VERSION 5.8 ;
BUSBITCHARS "[]" ;
DIVIDERCHAR "/" ;
UNITS
    DATABASE MICRONS 1000 ;
END UNITS

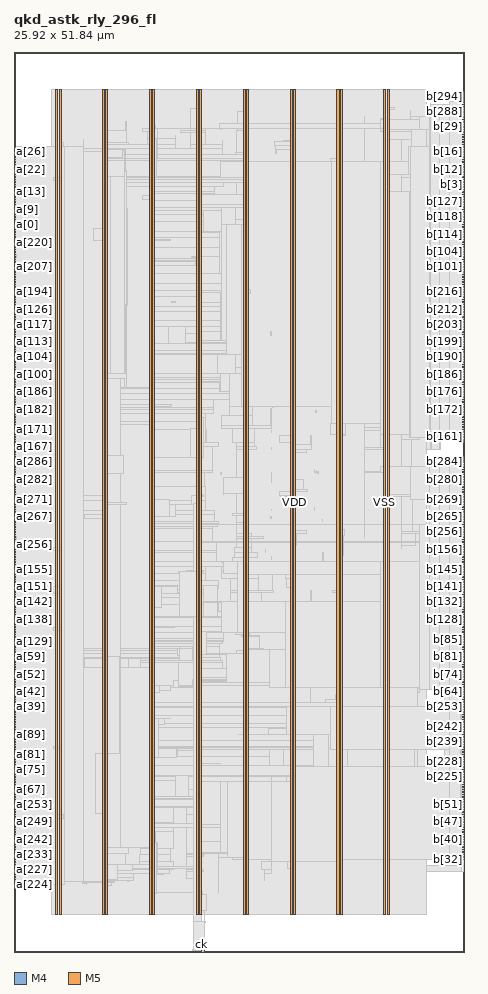
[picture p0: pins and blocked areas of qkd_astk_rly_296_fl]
MACRO qkd_astk_rly_296_fl
  FOREIGN qkd_astk_rly_296_fl 0 0 ;
  CLASS BLOCK ;
  SIZE 25.92 BY 51.84 ;
  PIN a[0]
    DIRECTION INPUT ;
    USE SIGNAL ;
    PORT
      LAYER M4 ;
        RECT  0 41.904 0.084 41.928 ;
    END
  END a[0]
  PIN a[100]
    DIRECTION INPUT ;
    USE SIGNAL ;
    PORT
      LAYER M4 ;
        RECT  0 33.264 0.084 33.288 ;
    END
  END a[100]
  PIN a[101]
    DIRECTION INPUT ;
    USE SIGNAL ;
    PORT
      LAYER M4 ;
        RECT  0 33.408 0.084 33.432 ;
    END
  END a[101]
  PIN a[102]
    DIRECTION INPUT ;
    USE SIGNAL ;
    PORT
      LAYER M4 ;
        RECT  0 33.552 0.084 33.576 ;
    END
  END a[102]
  PIN a[103]
    DIRECTION INPUT ;
    USE SIGNAL ;
    PORT
      LAYER M4 ;
        RECT  0 33.696 0.084 33.72 ;
    END
  END a[103]
  PIN a[104]
    DIRECTION INPUT ;
    USE SIGNAL ;
    PORT
      LAYER M4 ;
        RECT  0 33.84 0.084 33.864 ;
    END
  END a[104]
  PIN a[105]
    DIRECTION INPUT ;
    USE SIGNAL ;
    PORT
      LAYER M4 ;
        RECT  0 33.984 0.084 34.008 ;
    END
  END a[105]
  PIN a[106]
    DIRECTION INPUT ;
    USE SIGNAL ;
    PORT
      LAYER M4 ;
        RECT  0 34.128 0.084 34.152 ;
    END
  END a[106]
  PIN a[107]
    DIRECTION INPUT ;
    USE SIGNAL ;
    PORT
      LAYER M4 ;
        RECT  0 34.272 0.084 34.296 ;
    END
  END a[107]
  PIN a[108]
    DIRECTION INPUT ;
    USE SIGNAL ;
    PORT
      LAYER M4 ;
        RECT  0 34.416 0.084 34.44 ;
    END
  END a[108]
  PIN a[109]
    DIRECTION INPUT ;
    USE SIGNAL ;
    PORT
      LAYER M4 ;
        RECT  0 34.56 0.084 34.584 ;
    END
  END a[109]
  PIN a[10]
    DIRECTION INPUT ;
    USE SIGNAL ;
    PORT
      LAYER M4 ;
        RECT  0 43.344 0.084 43.368 ;
    END
  END a[10]
  PIN a[110]
    DIRECTION INPUT ;
    USE SIGNAL ;
    PORT
      LAYER M4 ;
        RECT  0 34.704 0.084 34.728 ;
    END
  END a[110]
  PIN a[111]
    DIRECTION INPUT ;
    USE SIGNAL ;
    PORT
      LAYER M4 ;
        RECT  0 34.848 0.084 34.872 ;
    END
  END a[111]
  PIN a[112]
    DIRECTION INPUT ;
    USE SIGNAL ;
    PORT
      LAYER M4 ;
        RECT  0 34.992 0.084 35.016 ;
    END
  END a[112]
  PIN a[113]
    DIRECTION INPUT ;
    USE SIGNAL ;
    PORT
      LAYER M4 ;
        RECT  0 35.136 0.084 35.16 ;
    END
  END a[113]
  PIN a[114]
    DIRECTION INPUT ;
    USE SIGNAL ;
    PORT
      LAYER M4 ;
        RECT  0 35.28 0.084 35.304 ;
    END
  END a[114]
  PIN a[115]
    DIRECTION INPUT ;
    USE SIGNAL ;
    PORT
      LAYER M4 ;
        RECT  0 35.424 0.084 35.448 ;
    END
  END a[115]
  PIN a[116]
    DIRECTION INPUT ;
    USE SIGNAL ;
    PORT
      LAYER M4 ;
        RECT  0 35.568 0.084 35.592 ;
    END
  END a[116]
  PIN a[117]
    DIRECTION INPUT ;
    USE SIGNAL ;
    PORT
      LAYER M4 ;
        RECT  0 35.712 0.084 35.736 ;
    END
  END a[117]
  PIN a[118]
    DIRECTION INPUT ;
    USE SIGNAL ;
    PORT
      LAYER M4 ;
        RECT  0 35.856 0.084 35.88 ;
    END
  END a[118]
  PIN a[119]
    DIRECTION INPUT ;
    USE SIGNAL ;
    PORT
      LAYER M4 ;
        RECT  0 36 0.084 36.024 ;
    END
  END a[119]
  PIN a[11]
    DIRECTION INPUT ;
    USE SIGNAL ;
    PORT
      LAYER M4 ;
        RECT  0 43.488 0.084 43.512 ;
    END
  END a[11]
  PIN a[120]
    DIRECTION INPUT ;
    USE SIGNAL ;
    PORT
      LAYER M4 ;
        RECT  0 36.144 0.084 36.168 ;
    END
  END a[120]
  PIN a[121]
    DIRECTION INPUT ;
    USE SIGNAL ;
    PORT
      LAYER M4 ;
        RECT  0 36.288 0.084 36.312 ;
    END
  END a[121]
  PIN a[122]
    DIRECTION INPUT ;
    USE SIGNAL ;
    PORT
      LAYER M4 ;
        RECT  0 36.432 0.084 36.456 ;
    END
  END a[122]
  PIN a[123]
    DIRECTION INPUT ;
    USE SIGNAL ;
    PORT
      LAYER M4 ;
        RECT  0 36.576 0.084 36.6 ;
    END
  END a[123]
  PIN a[124]
    DIRECTION INPUT ;
    USE SIGNAL ;
    PORT
      LAYER M4 ;
        RECT  0 36.72 0.084 36.744 ;
    END
  END a[124]
  PIN a[125]
    DIRECTION INPUT ;
    USE SIGNAL ;
    PORT
      LAYER M4 ;
        RECT  0 36.864 0.084 36.888 ;
    END
  END a[125]
  PIN a[126]
    DIRECTION INPUT ;
    USE SIGNAL ;
    PORT
      LAYER M4 ;
        RECT  0 37.008 0.084 37.032 ;
    END
  END a[126]
  PIN a[127]
    DIRECTION INPUT ;
    USE SIGNAL ;
    PORT
      LAYER M4 ;
        RECT  0 37.152 0.084 37.176 ;
    END
  END a[127]
  PIN a[128]
    DIRECTION INPUT ;
    USE SIGNAL ;
    PORT
      LAYER M4 ;
        RECT  0 17.712 0.084 17.736 ;
    END
  END a[128]
  PIN a[129]
    DIRECTION INPUT ;
    USE SIGNAL ;
    PORT
      LAYER M4 ;
        RECT  0 17.856 0.084 17.88 ;
    END
  END a[129]
  PIN a[12]
    DIRECTION INPUT ;
    USE SIGNAL ;
    PORT
      LAYER M4 ;
        RECT  0 43.632 0.084 43.656 ;
    END
  END a[12]
  PIN a[130]
    DIRECTION INPUT ;
    USE SIGNAL ;
    PORT
      LAYER M4 ;
        RECT  0 18 0.084 18.024 ;
    END
  END a[130]
  PIN a[131]
    DIRECTION INPUT ;
    USE SIGNAL ;
    PORT
      LAYER M4 ;
        RECT  0 18.144 0.084 18.168 ;
    END
  END a[131]
  PIN a[132]
    DIRECTION INPUT ;
    USE SIGNAL ;
    PORT
      LAYER M4 ;
        RECT  0 18.288 0.084 18.312 ;
    END
  END a[132]
  PIN a[133]
    DIRECTION INPUT ;
    USE SIGNAL ;
    PORT
      LAYER M4 ;
        RECT  0 18.432 0.084 18.456 ;
    END
  END a[133]
  PIN a[134]
    DIRECTION INPUT ;
    USE SIGNAL ;
    PORT
      LAYER M4 ;
        RECT  0 18.576 0.084 18.6 ;
    END
  END a[134]
  PIN a[135]
    DIRECTION INPUT ;
    USE SIGNAL ;
    PORT
      LAYER M4 ;
        RECT  0 18.72 0.084 18.744 ;
    END
  END a[135]
  PIN a[136]
    DIRECTION INPUT ;
    USE SIGNAL ;
    PORT
      LAYER M4 ;
        RECT  0 18.864 0.084 18.888 ;
    END
  END a[136]
  PIN a[137]
    DIRECTION INPUT ;
    USE SIGNAL ;
    PORT
      LAYER M4 ;
        RECT  0 19.008 0.084 19.032 ;
    END
  END a[137]
  PIN a[138]
    DIRECTION INPUT ;
    USE SIGNAL ;
    PORT
      LAYER M4 ;
        RECT  0 19.152 0.084 19.176 ;
    END
  END a[138]
  PIN a[139]
    DIRECTION INPUT ;
    USE SIGNAL ;
    PORT
      LAYER M4 ;
        RECT  0 19.296 0.084 19.32 ;
    END
  END a[139]
  PIN a[13]
    DIRECTION INPUT ;
    USE SIGNAL ;
    PORT
      LAYER M4 ;
        RECT  0 43.776 0.084 43.8 ;
    END
  END a[13]
  PIN a[140]
    DIRECTION INPUT ;
    USE SIGNAL ;
    PORT
      LAYER M4 ;
        RECT  0 19.44 0.084 19.464 ;
    END
  END a[140]
  PIN a[141]
    DIRECTION INPUT ;
    USE SIGNAL ;
    PORT
      LAYER M4 ;
        RECT  0 19.584 0.084 19.608 ;
    END
  END a[141]
  PIN a[142]
    DIRECTION INPUT ;
    USE SIGNAL ;
    PORT
      LAYER M4 ;
        RECT  0 19.728 0.084 19.752 ;
    END
  END a[142]
  PIN a[143]
    DIRECTION INPUT ;
    USE SIGNAL ;
    PORT
      LAYER M4 ;
        RECT  0 19.872 0.084 19.896 ;
    END
  END a[143]
  PIN a[144]
    DIRECTION INPUT ;
    USE SIGNAL ;
    PORT
      LAYER M4 ;
        RECT  0 20.016 0.084 20.04 ;
    END
  END a[144]
  PIN a[145]
    DIRECTION INPUT ;
    USE SIGNAL ;
    PORT
      LAYER M4 ;
        RECT  0 20.16 0.084 20.184 ;
    END
  END a[145]
  PIN a[146]
    DIRECTION INPUT ;
    USE SIGNAL ;
    PORT
      LAYER M4 ;
        RECT  0 20.304 0.084 20.328 ;
    END
  END a[146]
  PIN a[147]
    DIRECTION INPUT ;
    USE SIGNAL ;
    PORT
      LAYER M4 ;
        RECT  0 20.448 0.084 20.472 ;
    END
  END a[147]
  PIN a[148]
    DIRECTION INPUT ;
    USE SIGNAL ;
    PORT
      LAYER M4 ;
        RECT  0 20.592 0.084 20.616 ;
    END
  END a[148]
  PIN a[149]
    DIRECTION INPUT ;
    USE SIGNAL ;
    PORT
      LAYER M4 ;
        RECT  0 20.736 0.084 20.76 ;
    END
  END a[149]
  PIN a[14]
    DIRECTION INPUT ;
    USE SIGNAL ;
    PORT
      LAYER M4 ;
        RECT  0 43.92 0.084 43.944 ;
    END
  END a[14]
  PIN a[150]
    DIRECTION INPUT ;
    USE SIGNAL ;
    PORT
      LAYER M4 ;
        RECT  0 20.88 0.084 20.904 ;
    END
  END a[150]
  PIN a[151]
    DIRECTION INPUT ;
    USE SIGNAL ;
    PORT
      LAYER M4 ;
        RECT  0 21.024 0.084 21.048 ;
    END
  END a[151]
  PIN a[152]
    DIRECTION INPUT ;
    USE SIGNAL ;
    PORT
      LAYER M4 ;
        RECT  0 21.168 0.084 21.192 ;
    END
  END a[152]
  PIN a[153]
    DIRECTION INPUT ;
    USE SIGNAL ;
    PORT
      LAYER M4 ;
        RECT  0 21.312 0.084 21.336 ;
    END
  END a[153]
  PIN a[154]
    DIRECTION INPUT ;
    USE SIGNAL ;
    PORT
      LAYER M4 ;
        RECT  0 21.456 0.084 21.48 ;
    END
  END a[154]
  PIN a[155]
    DIRECTION INPUT ;
    USE SIGNAL ;
    PORT
      LAYER M4 ;
        RECT  0 21.6 0.084 21.624 ;
    END
  END a[155]
  PIN a[156]
    DIRECTION INPUT ;
    USE SIGNAL ;
    PORT
      LAYER M4 ;
        RECT  0 21.744 0.084 21.768 ;
    END
  END a[156]
  PIN a[157]
    DIRECTION INPUT ;
    USE SIGNAL ;
    PORT
      LAYER M4 ;
        RECT  0 21.888 0.084 21.912 ;
    END
  END a[157]
  PIN a[158]
    DIRECTION INPUT ;
    USE SIGNAL ;
    PORT
      LAYER M4 ;
        RECT  0 22.032 0.084 22.056 ;
    END
  END a[158]
  PIN a[159]
    DIRECTION INPUT ;
    USE SIGNAL ;
    PORT
      LAYER M4 ;
        RECT  0 22.176 0.084 22.2 ;
    END
  END a[159]
  PIN a[15]
    DIRECTION INPUT ;
    USE SIGNAL ;
    PORT
      LAYER M4 ;
        RECT  0 44.064 0.084 44.088 ;
    END
  END a[15]
  PIN a[160]
    DIRECTION INPUT ;
    USE SIGNAL ;
    PORT
      LAYER M4 ;
        RECT  0 28.08 0.084 28.104 ;
    END
  END a[160]
  PIN a[161]
    DIRECTION INPUT ;
    USE SIGNAL ;
    PORT
      LAYER M4 ;
        RECT  0 28.224 0.084 28.248 ;
    END
  END a[161]
  PIN a[162]
    DIRECTION INPUT ;
    USE SIGNAL ;
    PORT
      LAYER M4 ;
        RECT  0 28.368 0.084 28.392 ;
    END
  END a[162]
  PIN a[163]
    DIRECTION INPUT ;
    USE SIGNAL ;
    PORT
      LAYER M4 ;
        RECT  0 28.512 0.084 28.536 ;
    END
  END a[163]
  PIN a[164]
    DIRECTION INPUT ;
    USE SIGNAL ;
    PORT
      LAYER M4 ;
        RECT  0 28.656 0.084 28.68 ;
    END
  END a[164]
  PIN a[165]
    DIRECTION INPUT ;
    USE SIGNAL ;
    PORT
      LAYER M4 ;
        RECT  0 28.8 0.084 28.824 ;
    END
  END a[165]
  PIN a[166]
    DIRECTION INPUT ;
    USE SIGNAL ;
    PORT
      LAYER M4 ;
        RECT  0 28.944 0.084 28.968 ;
    END
  END a[166]
  PIN a[167]
    DIRECTION INPUT ;
    USE SIGNAL ;
    PORT
      LAYER M4 ;
        RECT  0 29.088 0.084 29.112 ;
    END
  END a[167]
  PIN a[168]
    DIRECTION INPUT ;
    USE SIGNAL ;
    PORT
      LAYER M4 ;
        RECT  0 29.232 0.084 29.256 ;
    END
  END a[168]
  PIN a[169]
    DIRECTION INPUT ;
    USE SIGNAL ;
    PORT
      LAYER M4 ;
        RECT  0 29.376 0.084 29.4 ;
    END
  END a[169]
  PIN a[16]
    DIRECTION INPUT ;
    USE SIGNAL ;
    PORT
      LAYER M4 ;
        RECT  0 44.208 0.084 44.232 ;
    END
  END a[16]
  PIN a[170]
    DIRECTION INPUT ;
    USE SIGNAL ;
    PORT
      LAYER M4 ;
        RECT  0 29.52 0.084 29.544 ;
    END
  END a[170]
  PIN a[171]
    DIRECTION INPUT ;
    USE SIGNAL ;
    PORT
      LAYER M4 ;
        RECT  0 29.664 0.084 29.688 ;
    END
  END a[171]
  PIN a[172]
    DIRECTION INPUT ;
    USE SIGNAL ;
    PORT
      LAYER M4 ;
        RECT  0 29.808 0.084 29.832 ;
    END
  END a[172]
  PIN a[173]
    DIRECTION INPUT ;
    USE SIGNAL ;
    PORT
      LAYER M4 ;
        RECT  0 29.952 0.084 29.976 ;
    END
  END a[173]
  PIN a[174]
    DIRECTION INPUT ;
    USE SIGNAL ;
    PORT
      LAYER M4 ;
        RECT  0 30.096 0.084 30.12 ;
    END
  END a[174]
  PIN a[175]
    DIRECTION INPUT ;
    USE SIGNAL ;
    PORT
      LAYER M4 ;
        RECT  0 30.24 0.084 30.264 ;
    END
  END a[175]
  PIN a[176]
    DIRECTION INPUT ;
    USE SIGNAL ;
    PORT
      LAYER M4 ;
        RECT  0 30.384 0.084 30.408 ;
    END
  END a[176]
  PIN a[177]
    DIRECTION INPUT ;
    USE SIGNAL ;
    PORT
      LAYER M4 ;
        RECT  0 30.528 0.084 30.552 ;
    END
  END a[177]
  PIN a[178]
    DIRECTION INPUT ;
    USE SIGNAL ;
    PORT
      LAYER M4 ;
        RECT  0 30.672 0.084 30.696 ;
    END
  END a[178]
  PIN a[179]
    DIRECTION INPUT ;
    USE SIGNAL ;
    PORT
      LAYER M4 ;
        RECT  0 30.816 0.084 30.84 ;
    END
  END a[179]
  PIN a[17]
    DIRECTION INPUT ;
    USE SIGNAL ;
    PORT
      LAYER M4 ;
        RECT  0 44.352 0.084 44.376 ;
    END
  END a[17]
  PIN a[180]
    DIRECTION INPUT ;
    USE SIGNAL ;
    PORT
      LAYER M4 ;
        RECT  0 30.96 0.084 30.984 ;
    END
  END a[180]
  PIN a[181]
    DIRECTION INPUT ;
    USE SIGNAL ;
    PORT
      LAYER M4 ;
        RECT  0 31.104 0.084 31.128 ;
    END
  END a[181]
  PIN a[182]
    DIRECTION INPUT ;
    USE SIGNAL ;
    PORT
      LAYER M4 ;
        RECT  0 31.248 0.084 31.272 ;
    END
  END a[182]
  PIN a[183]
    DIRECTION INPUT ;
    USE SIGNAL ;
    PORT
      LAYER M4 ;
        RECT  0 31.392 0.084 31.416 ;
    END
  END a[183]
  PIN a[184]
    DIRECTION INPUT ;
    USE SIGNAL ;
    PORT
      LAYER M4 ;
        RECT  0 31.536 0.084 31.56 ;
    END
  END a[184]
  PIN a[185]
    DIRECTION INPUT ;
    USE SIGNAL ;
    PORT
      LAYER M4 ;
        RECT  0 31.68 0.084 31.704 ;
    END
  END a[185]
  PIN a[186]
    DIRECTION INPUT ;
    USE SIGNAL ;
    PORT
      LAYER M4 ;
        RECT  0 31.824 0.084 31.848 ;
    END
  END a[186]
  PIN a[187]
    DIRECTION INPUT ;
    USE SIGNAL ;
    PORT
      LAYER M4 ;
        RECT  0 31.968 0.084 31.992 ;
    END
  END a[187]
  PIN a[188]
    DIRECTION INPUT ;
    USE SIGNAL ;
    PORT
      LAYER M4 ;
        RECT  0 32.112 0.084 32.136 ;
    END
  END a[188]
  PIN a[189]
    DIRECTION INPUT ;
    USE SIGNAL ;
    PORT
      LAYER M4 ;
        RECT  0 32.256 0.084 32.28 ;
    END
  END a[189]
  PIN a[18]
    DIRECTION INPUT ;
    USE SIGNAL ;
    PORT
      LAYER M4 ;
        RECT  0 44.496 0.084 44.52 ;
    END
  END a[18]
  PIN a[190]
    DIRECTION INPUT ;
    USE SIGNAL ;
    PORT
      LAYER M4 ;
        RECT  0 32.4 0.084 32.424 ;
    END
  END a[190]
  PIN a[191]
    DIRECTION INPUT ;
    USE SIGNAL ;
    PORT
      LAYER M4 ;
        RECT  0 32.544 0.084 32.568 ;
    END
  END a[191]
  PIN a[192]
    DIRECTION INPUT ;
    USE SIGNAL ;
    PORT
      LAYER M4 ;
        RECT  0 37.296 0.084 37.32 ;
    END
  END a[192]
  PIN a[193]
    DIRECTION INPUT ;
    USE SIGNAL ;
    PORT
      LAYER M4 ;
        RECT  0 37.44 0.084 37.464 ;
    END
  END a[193]
  PIN a[194]
    DIRECTION INPUT ;
    USE SIGNAL ;
    PORT
      LAYER M4 ;
        RECT  0 37.584 0.084 37.608 ;
    END
  END a[194]
  PIN a[195]
    DIRECTION INPUT ;
    USE SIGNAL ;
    PORT
      LAYER M4 ;
        RECT  0 37.728 0.084 37.752 ;
    END
  END a[195]
  PIN a[196]
    DIRECTION INPUT ;
    USE SIGNAL ;
    PORT
      LAYER M4 ;
        RECT  0 37.872 0.084 37.896 ;
    END
  END a[196]
  PIN a[197]
    DIRECTION INPUT ;
    USE SIGNAL ;
    PORT
      LAYER M4 ;
        RECT  0 38.016 0.084 38.04 ;
    END
  END a[197]
  PIN a[198]
    DIRECTION INPUT ;
    USE SIGNAL ;
    PORT
      LAYER M4 ;
        RECT  0 38.16 0.084 38.184 ;
    END
  END a[198]
  PIN a[199]
    DIRECTION INPUT ;
    USE SIGNAL ;
    PORT
      LAYER M4 ;
        RECT  0 38.304 0.084 38.328 ;
    END
  END a[199]
  PIN a[19]
    DIRECTION INPUT ;
    USE SIGNAL ;
    PORT
      LAYER M4 ;
        RECT  0 44.64 0.084 44.664 ;
    END
  END a[19]
  PIN a[1]
    DIRECTION INPUT ;
    USE SIGNAL ;
    PORT
      LAYER M4 ;
        RECT  0 42.048 0.084 42.072 ;
    END
  END a[1]
  PIN a[200]
    DIRECTION INPUT ;
    USE SIGNAL ;
    PORT
      LAYER M4 ;
        RECT  0 38.448 0.084 38.472 ;
    END
  END a[200]
  PIN a[201]
    DIRECTION INPUT ;
    USE SIGNAL ;
    PORT
      LAYER M4 ;
        RECT  0 38.592 0.084 38.616 ;
    END
  END a[201]
  PIN a[202]
    DIRECTION INPUT ;
    USE SIGNAL ;
    PORT
      LAYER M4 ;
        RECT  0 38.736 0.084 38.76 ;
    END
  END a[202]
  PIN a[203]
    DIRECTION INPUT ;
    USE SIGNAL ;
    PORT
      LAYER M4 ;
        RECT  0 38.88 0.084 38.904 ;
    END
  END a[203]
  PIN a[204]
    DIRECTION INPUT ;
    USE SIGNAL ;
    PORT
      LAYER M4 ;
        RECT  0 39.024 0.084 39.048 ;
    END
  END a[204]
  PIN a[205]
    DIRECTION INPUT ;
    USE SIGNAL ;
    PORT
      LAYER M4 ;
        RECT  0 39.168 0.084 39.192 ;
    END
  END a[205]
  PIN a[206]
    DIRECTION INPUT ;
    USE SIGNAL ;
    PORT
      LAYER M4 ;
        RECT  0 39.312 0.084 39.336 ;
    END
  END a[206]
  PIN a[207]
    DIRECTION INPUT ;
    USE SIGNAL ;
    PORT
      LAYER M4 ;
        RECT  0 39.456 0.084 39.48 ;
    END
  END a[207]
  PIN a[208]
    DIRECTION INPUT ;
    USE SIGNAL ;
    PORT
      LAYER M4 ;
        RECT  0 39.6 0.084 39.624 ;
    END
  END a[208]
  PIN a[209]
    DIRECTION INPUT ;
    USE SIGNAL ;
    PORT
      LAYER M4 ;
        RECT  0 39.744 0.084 39.768 ;
    END
  END a[209]
  PIN a[20]
    DIRECTION INPUT ;
    USE SIGNAL ;
    PORT
      LAYER M4 ;
        RECT  0 44.784 0.084 44.808 ;
    END
  END a[20]
  PIN a[210]
    DIRECTION INPUT ;
    USE SIGNAL ;
    PORT
      LAYER M4 ;
        RECT  0 39.888 0.084 39.912 ;
    END
  END a[210]
  PIN a[211]
    DIRECTION INPUT ;
    USE SIGNAL ;
    PORT
      LAYER M4 ;
        RECT  0 40.032 0.084 40.056 ;
    END
  END a[211]
  PIN a[212]
    DIRECTION INPUT ;
    USE SIGNAL ;
    PORT
      LAYER M4 ;
        RECT  0 40.176 0.084 40.2 ;
    END
  END a[212]
  PIN a[213]
    DIRECTION INPUT ;
    USE SIGNAL ;
    PORT
      LAYER M4 ;
        RECT  0 40.32 0.084 40.344 ;
    END
  END a[213]
  PIN a[214]
    DIRECTION INPUT ;
    USE SIGNAL ;
    PORT
      LAYER M4 ;
        RECT  0 40.464 0.084 40.488 ;
    END
  END a[214]
  PIN a[215]
    DIRECTION INPUT ;
    USE SIGNAL ;
    PORT
      LAYER M4 ;
        RECT  0 40.608 0.084 40.632 ;
    END
  END a[215]
  PIN a[216]
    DIRECTION INPUT ;
    USE SIGNAL ;
    PORT
      LAYER M4 ;
        RECT  0 40.752 0.084 40.776 ;
    END
  END a[216]
  PIN a[217]
    DIRECTION INPUT ;
    USE SIGNAL ;
    PORT
      LAYER M4 ;
        RECT  0 40.896 0.084 40.92 ;
    END
  END a[217]
  PIN a[218]
    DIRECTION INPUT ;
    USE SIGNAL ;
    PORT
      LAYER M4 ;
        RECT  0 41.04 0.084 41.064 ;
    END
  END a[218]
  PIN a[219]
    DIRECTION INPUT ;
    USE SIGNAL ;
    PORT
      LAYER M4 ;
        RECT  0 41.184 0.084 41.208 ;
    END
  END a[219]
  PIN a[21]
    DIRECTION INPUT ;
    USE SIGNAL ;
    PORT
      LAYER M4 ;
        RECT  0 44.928 0.084 44.952 ;
    END
  END a[21]
  PIN a[220]
    DIRECTION INPUT ;
    USE SIGNAL ;
    PORT
      LAYER M4 ;
        RECT  0 41.328 0.084 41.352 ;
    END
  END a[220]
  PIN a[221]
    DIRECTION INPUT ;
    USE SIGNAL ;
    PORT
      LAYER M4 ;
        RECT  0 41.472 0.084 41.496 ;
    END
  END a[221]
  PIN a[222]
    DIRECTION INPUT ;
    USE SIGNAL ;
    PORT
      LAYER M4 ;
        RECT  0 41.616 0.084 41.64 ;
    END
  END a[222]
  PIN a[223]
    DIRECTION INPUT ;
    USE SIGNAL ;
    PORT
      LAYER M4 ;
        RECT  0 41.76 0.084 41.784 ;
    END
  END a[223]
  PIN a[224]
    DIRECTION INPUT ;
    USE SIGNAL ;
    PORT
      LAYER M4 ;
        RECT  0 3.888 0.084 3.912 ;
    END
  END a[224]
  PIN a[225]
    DIRECTION INPUT ;
    USE SIGNAL ;
    PORT
      LAYER M4 ;
        RECT  0 4.032 0.084 4.056 ;
    END
  END a[225]
  PIN a[226]
    DIRECTION INPUT ;
    USE SIGNAL ;
    PORT
      LAYER M4 ;
        RECT  0 4.176 0.084 4.2 ;
    END
  END a[226]
  PIN a[227]
    DIRECTION INPUT ;
    USE SIGNAL ;
    PORT
      LAYER M4 ;
        RECT  0 4.32 0.084 4.344 ;
    END
  END a[227]
  PIN a[228]
    DIRECTION INPUT ;
    USE SIGNAL ;
    PORT
      LAYER M4 ;
        RECT  0 4.464 0.084 4.488 ;
    END
  END a[228]
  PIN a[229]
    DIRECTION INPUT ;
    USE SIGNAL ;
    PORT
      LAYER M4 ;
        RECT  0 4.608 0.084 4.632 ;
    END
  END a[229]
  PIN a[22]
    DIRECTION INPUT ;
    USE SIGNAL ;
    PORT
      LAYER M4 ;
        RECT  0 45.072 0.084 45.096 ;
    END
  END a[22]
  PIN a[230]
    DIRECTION INPUT ;
    USE SIGNAL ;
    PORT
      LAYER M4 ;
        RECT  0 4.752 0.084 4.776 ;
    END
  END a[230]
  PIN a[231]
    DIRECTION INPUT ;
    USE SIGNAL ;
    PORT
      LAYER M4 ;
        RECT  0 4.896 0.084 4.92 ;
    END
  END a[231]
  PIN a[232]
    DIRECTION INPUT ;
    USE SIGNAL ;
    PORT
      LAYER M4 ;
        RECT  0 5.04 0.084 5.064 ;
    END
  END a[232]
  PIN a[233]
    DIRECTION INPUT ;
    USE SIGNAL ;
    PORT
      LAYER M4 ;
        RECT  0 5.184 0.084 5.208 ;
    END
  END a[233]
  PIN a[234]
    DIRECTION INPUT ;
    USE SIGNAL ;
    PORT
      LAYER M4 ;
        RECT  0 5.328 0.084 5.352 ;
    END
  END a[234]
  PIN a[235]
    DIRECTION INPUT ;
    USE SIGNAL ;
    PORT
      LAYER M4 ;
        RECT  0 5.472 0.084 5.496 ;
    END
  END a[235]
  PIN a[236]
    DIRECTION INPUT ;
    USE SIGNAL ;
    PORT
      LAYER M4 ;
        RECT  0 5.616 0.084 5.64 ;
    END
  END a[236]
  PIN a[237]
    DIRECTION INPUT ;
    USE SIGNAL ;
    PORT
      LAYER M4 ;
        RECT  0 5.76 0.084 5.784 ;
    END
  END a[237]
  PIN a[238]
    DIRECTION INPUT ;
    USE SIGNAL ;
    PORT
      LAYER M4 ;
        RECT  0 5.904 0.084 5.928 ;
    END
  END a[238]
  PIN a[239]
    DIRECTION INPUT ;
    USE SIGNAL ;
    PORT
      LAYER M4 ;
        RECT  0 6.048 0.084 6.072 ;
    END
  END a[239]
  PIN a[23]
    DIRECTION INPUT ;
    USE SIGNAL ;
    PORT
      LAYER M4 ;
        RECT  0 45.216 0.084 45.24 ;
    END
  END a[23]
  PIN a[240]
    DIRECTION INPUT ;
    USE SIGNAL ;
    PORT
      LAYER M4 ;
        RECT  0 6.192 0.084 6.216 ;
    END
  END a[240]
  PIN a[241]
    DIRECTION INPUT ;
    USE SIGNAL ;
    PORT
      LAYER M4 ;
        RECT  0 6.336 0.084 6.36 ;
    END
  END a[241]
  PIN a[242]
    DIRECTION INPUT ;
    USE SIGNAL ;
    PORT
      LAYER M4 ;
        RECT  0 6.48 0.084 6.504 ;
    END
  END a[242]
  PIN a[243]
    DIRECTION INPUT ;
    USE SIGNAL ;
    PORT
      LAYER M4 ;
        RECT  0 6.624 0.084 6.648 ;
    END
  END a[243]
  PIN a[244]
    DIRECTION INPUT ;
    USE SIGNAL ;
    PORT
      LAYER M4 ;
        RECT  0 6.768 0.084 6.792 ;
    END
  END a[244]
  PIN a[245]
    DIRECTION INPUT ;
    USE SIGNAL ;
    PORT
      LAYER M4 ;
        RECT  0 6.912 0.084 6.936 ;
    END
  END a[245]
  PIN a[246]
    DIRECTION INPUT ;
    USE SIGNAL ;
    PORT
      LAYER M4 ;
        RECT  0 7.056 0.084 7.08 ;
    END
  END a[246]
  PIN a[247]
    DIRECTION INPUT ;
    USE SIGNAL ;
    PORT
      LAYER M4 ;
        RECT  0 7.2 0.084 7.224 ;
    END
  END a[247]
  PIN a[248]
    DIRECTION INPUT ;
    USE SIGNAL ;
    PORT
      LAYER M4 ;
        RECT  0 7.344 0.084 7.368 ;
    END
  END a[248]
  PIN a[249]
    DIRECTION INPUT ;
    USE SIGNAL ;
    PORT
      LAYER M4 ;
        RECT  0 7.488 0.084 7.512 ;
    END
  END a[249]
  PIN a[24]
    DIRECTION INPUT ;
    USE SIGNAL ;
    PORT
      LAYER M4 ;
        RECT  0 45.36 0.084 45.384 ;
    END
  END a[24]
  PIN a[250]
    DIRECTION INPUT ;
    USE SIGNAL ;
    PORT
      LAYER M4 ;
        RECT  0 7.632 0.084 7.656 ;
    END
  END a[250]
  PIN a[251]
    DIRECTION INPUT ;
    USE SIGNAL ;
    PORT
      LAYER M4 ;
        RECT  0 7.776 0.084 7.8 ;
    END
  END a[251]
  PIN a[252]
    DIRECTION INPUT ;
    USE SIGNAL ;
    PORT
      LAYER M4 ;
        RECT  0 7.92 0.084 7.944 ;
    END
  END a[252]
  PIN a[253]
    DIRECTION INPUT ;
    USE SIGNAL ;
    PORT
      LAYER M4 ;
        RECT  0 8.064 0.084 8.088 ;
    END
  END a[253]
  PIN a[254]
    DIRECTION INPUT ;
    USE SIGNAL ;
    PORT
      LAYER M4 ;
        RECT  0 8.208 0.084 8.232 ;
    END
  END a[254]
  PIN a[255]
    DIRECTION INPUT ;
    USE SIGNAL ;
    PORT
      LAYER M4 ;
        RECT  0 8.352 0.084 8.376 ;
    END
  END a[255]
  PIN a[256]
    DIRECTION INPUT ;
    USE SIGNAL ;
    PORT
      LAYER M4 ;
        RECT  0 23.472 0.084 23.496 ;
    END
  END a[256]
  PIN a[257]
    DIRECTION INPUT ;
    USE SIGNAL ;
    PORT
      LAYER M4 ;
        RECT  0 23.616 0.084 23.64 ;
    END
  END a[257]
  PIN a[258]
    DIRECTION INPUT ;
    USE SIGNAL ;
    PORT
      LAYER M4 ;
        RECT  0 23.76 0.084 23.784 ;
    END
  END a[258]
  PIN a[259]
    DIRECTION INPUT ;
    USE SIGNAL ;
    PORT
      LAYER M4 ;
        RECT  0 23.904 0.084 23.928 ;
    END
  END a[259]
  PIN a[25]
    DIRECTION INPUT ;
    USE SIGNAL ;
    PORT
      LAYER M4 ;
        RECT  0 45.504 0.084 45.528 ;
    END
  END a[25]
  PIN a[260]
    DIRECTION INPUT ;
    USE SIGNAL ;
    PORT
      LAYER M4 ;
        RECT  0 24.048 0.084 24.072 ;
    END
  END a[260]
  PIN a[261]
    DIRECTION INPUT ;
    USE SIGNAL ;
    PORT
      LAYER M4 ;
        RECT  0 24.192 0.084 24.216 ;
    END
  END a[261]
  PIN a[262]
    DIRECTION INPUT ;
    USE SIGNAL ;
    PORT
      LAYER M4 ;
        RECT  0 24.336 0.084 24.36 ;
    END
  END a[262]
  PIN a[263]
    DIRECTION INPUT ;
    USE SIGNAL ;
    PORT
      LAYER M4 ;
        RECT  0 24.48 0.084 24.504 ;
    END
  END a[263]
  PIN a[264]
    DIRECTION INPUT ;
    USE SIGNAL ;
    PORT
      LAYER M4 ;
        RECT  0 24.624 0.084 24.648 ;
    END
  END a[264]
  PIN a[265]
    DIRECTION INPUT ;
    USE SIGNAL ;
    PORT
      LAYER M4 ;
        RECT  0 24.768 0.084 24.792 ;
    END
  END a[265]
  PIN a[266]
    DIRECTION INPUT ;
    USE SIGNAL ;
    PORT
      LAYER M4 ;
        RECT  0 24.912 0.084 24.936 ;
    END
  END a[266]
  PIN a[267]
    DIRECTION INPUT ;
    USE SIGNAL ;
    PORT
      LAYER M4 ;
        RECT  0 25.056 0.084 25.08 ;
    END
  END a[267]
  PIN a[268]
    DIRECTION INPUT ;
    USE SIGNAL ;
    PORT
      LAYER M4 ;
        RECT  0 25.2 0.084 25.224 ;
    END
  END a[268]
  PIN a[269]
    DIRECTION INPUT ;
    USE SIGNAL ;
    PORT
      LAYER M4 ;
        RECT  0 25.344 0.084 25.368 ;
    END
  END a[269]
  PIN a[26]
    DIRECTION INPUT ;
    USE SIGNAL ;
    PORT
      LAYER M4 ;
        RECT  0 45.648 0.084 45.672 ;
    END
  END a[26]
  PIN a[270]
    DIRECTION INPUT ;
    USE SIGNAL ;
    PORT
      LAYER M4 ;
        RECT  0 25.488 0.084 25.512 ;
    END
  END a[270]
  PIN a[271]
    DIRECTION INPUT ;
    USE SIGNAL ;
    PORT
      LAYER M4 ;
        RECT  0 25.632 0.084 25.656 ;
    END
  END a[271]
  PIN a[272]
    DIRECTION INPUT ;
    USE SIGNAL ;
    PORT
      LAYER M4 ;
        RECT  0 25.776 0.084 25.8 ;
    END
  END a[272]
  PIN a[273]
    DIRECTION INPUT ;
    USE SIGNAL ;
    PORT
      LAYER M4 ;
        RECT  0 25.92 0.084 25.944 ;
    END
  END a[273]
  PIN a[274]
    DIRECTION INPUT ;
    USE SIGNAL ;
    PORT
      LAYER M4 ;
        RECT  0 26.064 0.084 26.088 ;
    END
  END a[274]
  PIN a[275]
    DIRECTION INPUT ;
    USE SIGNAL ;
    PORT
      LAYER M4 ;
        RECT  0 26.208 0.084 26.232 ;
    END
  END a[275]
  PIN a[276]
    DIRECTION INPUT ;
    USE SIGNAL ;
    PORT
      LAYER M4 ;
        RECT  0 26.352 0.084 26.376 ;
    END
  END a[276]
  PIN a[277]
    DIRECTION INPUT ;
    USE SIGNAL ;
    PORT
      LAYER M4 ;
        RECT  0 26.496 0.084 26.52 ;
    END
  END a[277]
  PIN a[278]
    DIRECTION INPUT ;
    USE SIGNAL ;
    PORT
      LAYER M4 ;
        RECT  0 26.64 0.084 26.664 ;
    END
  END a[278]
  PIN a[279]
    DIRECTION INPUT ;
    USE SIGNAL ;
    PORT
      LAYER M4 ;
        RECT  0 26.784 0.084 26.808 ;
    END
  END a[279]
  PIN a[27]
    DIRECTION INPUT ;
    USE SIGNAL ;
    PORT
      LAYER M4 ;
        RECT  0 45.792 0.084 45.816 ;
    END
  END a[27]
  PIN a[280]
    DIRECTION INPUT ;
    USE SIGNAL ;
    PORT
      LAYER M4 ;
        RECT  0 26.928 0.084 26.952 ;
    END
  END a[280]
  PIN a[281]
    DIRECTION INPUT ;
    USE SIGNAL ;
    PORT
      LAYER M4 ;
        RECT  0 27.072 0.084 27.096 ;
    END
  END a[281]
  PIN a[282]
    DIRECTION INPUT ;
    USE SIGNAL ;
    PORT
      LAYER M4 ;
        RECT  0 27.216 0.084 27.24 ;
    END
  END a[282]
  PIN a[283]
    DIRECTION INPUT ;
    USE SIGNAL ;
    PORT
      LAYER M4 ;
        RECT  0 27.36 0.084 27.384 ;
    END
  END a[283]
  PIN a[284]
    DIRECTION INPUT ;
    USE SIGNAL ;
    PORT
      LAYER M4 ;
        RECT  0 27.504 0.084 27.528 ;
    END
  END a[284]
  PIN a[285]
    DIRECTION INPUT ;
    USE SIGNAL ;
    PORT
      LAYER M4 ;
        RECT  0 27.648 0.084 27.672 ;
    END
  END a[285]
  PIN a[286]
    DIRECTION INPUT ;
    USE SIGNAL ;
    PORT
      LAYER M4 ;
        RECT  0 27.792 0.084 27.816 ;
    END
  END a[286]
  PIN a[287]
    DIRECTION INPUT ;
    USE SIGNAL ;
    PORT
      LAYER M4 ;
        RECT  0 27.936 0.084 27.96 ;
    END
  END a[287]
  PIN a[288]
    DIRECTION INPUT ;
    USE SIGNAL ;
    PORT
      LAYER M4 ;
        RECT  0 22.32 0.084 22.344 ;
    END
  END a[288]
  PIN a[289]
    DIRECTION INPUT ;
    USE SIGNAL ;
    PORT
      LAYER M4 ;
        RECT  0 22.464 0.084 22.488 ;
    END
  END a[289]
  PIN a[28]
    DIRECTION INPUT ;
    USE SIGNAL ;
    PORT
      LAYER M4 ;
        RECT  0 45.936 0.084 45.96 ;
    END
  END a[28]
  PIN a[290]
    DIRECTION INPUT ;
    USE SIGNAL ;
    PORT
      LAYER M4 ;
        RECT  0 22.608 0.084 22.632 ;
    END
  END a[290]
  PIN a[291]
    DIRECTION INPUT ;
    USE SIGNAL ;
    PORT
      LAYER M4 ;
        RECT  0 22.752 0.084 22.776 ;
    END
  END a[291]
  PIN a[292]
    DIRECTION INPUT ;
    USE SIGNAL ;
    PORT
      LAYER M4 ;
        RECT  0 22.896 0.084 22.92 ;
    END
  END a[292]
  PIN a[293]
    DIRECTION INPUT ;
    USE SIGNAL ;
    PORT
      LAYER M4 ;
        RECT  0 23.04 0.084 23.064 ;
    END
  END a[293]
  PIN a[294]
    DIRECTION INPUT ;
    USE SIGNAL ;
    PORT
      LAYER M4 ;
        RECT  0 23.184 0.084 23.208 ;
    END
  END a[294]
  PIN a[295]
    DIRECTION INPUT ;
    USE SIGNAL ;
    PORT
      LAYER M4 ;
        RECT  0 23.328 0.084 23.352 ;
    END
  END a[295]
  PIN a[29]
    DIRECTION INPUT ;
    USE SIGNAL ;
    PORT
      LAYER M4 ;
        RECT  0 46.08 0.084 46.104 ;
    END
  END a[29]
  PIN a[2]
    DIRECTION INPUT ;
    USE SIGNAL ;
    PORT
      LAYER M4 ;
        RECT  0 42.192 0.084 42.216 ;
    END
  END a[2]
  PIN a[30]
    DIRECTION INPUT ;
    USE SIGNAL ;
    PORT
      LAYER M4 ;
        RECT  0 46.224 0.084 46.248 ;
    END
  END a[30]
  PIN a[31]
    DIRECTION INPUT ;
    USE SIGNAL ;
    PORT
      LAYER M4 ;
        RECT  0 46.368 0.084 46.392 ;
    END
  END a[31]
  PIN a[32]
    DIRECTION INPUT ;
    USE SIGNAL ;
    PORT
      LAYER M4 ;
        RECT  0 13.104 0.084 13.128 ;
    END
  END a[32]
  PIN a[33]
    DIRECTION INPUT ;
    USE SIGNAL ;
    PORT
      LAYER M4 ;
        RECT  0 13.248 0.084 13.272 ;
    END
  END a[33]
  PIN a[34]
    DIRECTION INPUT ;
    USE SIGNAL ;
    PORT
      LAYER M4 ;
        RECT  0 13.392 0.084 13.416 ;
    END
  END a[34]
  PIN a[35]
    DIRECTION INPUT ;
    USE SIGNAL ;
    PORT
      LAYER M4 ;
        RECT  0 13.536 0.084 13.56 ;
    END
  END a[35]
  PIN a[36]
    DIRECTION INPUT ;
    USE SIGNAL ;
    PORT
      LAYER M4 ;
        RECT  0 13.68 0.084 13.704 ;
    END
  END a[36]
  PIN a[37]
    DIRECTION INPUT ;
    USE SIGNAL ;
    PORT
      LAYER M4 ;
        RECT  0 13.824 0.084 13.848 ;
    END
  END a[37]
  PIN a[38]
    DIRECTION INPUT ;
    USE SIGNAL ;
    PORT
      LAYER M4 ;
        RECT  0 13.968 0.084 13.992 ;
    END
  END a[38]
  PIN a[39]
    DIRECTION INPUT ;
    USE SIGNAL ;
    PORT
      LAYER M4 ;
        RECT  0 14.112 0.084 14.136 ;
    END
  END a[39]
  PIN a[3]
    DIRECTION INPUT ;
    USE SIGNAL ;
    PORT
      LAYER M4 ;
        RECT  0 42.336 0.084 42.36 ;
    END
  END a[3]
  PIN a[40]
    DIRECTION INPUT ;
    USE SIGNAL ;
    PORT
      LAYER M4 ;
        RECT  0 14.256 0.084 14.28 ;
    END
  END a[40]
  PIN a[41]
    DIRECTION INPUT ;
    USE SIGNAL ;
    PORT
      LAYER M4 ;
        RECT  0 14.4 0.084 14.424 ;
    END
  END a[41]
  PIN a[42]
    DIRECTION INPUT ;
    USE SIGNAL ;
    PORT
      LAYER M4 ;
        RECT  0 14.544 0.084 14.568 ;
    END
  END a[42]
  PIN a[43]
    DIRECTION INPUT ;
    USE SIGNAL ;
    PORT
      LAYER M4 ;
        RECT  0 14.688 0.084 14.712 ;
    END
  END a[43]
  PIN a[44]
    DIRECTION INPUT ;
    USE SIGNAL ;
    PORT
      LAYER M4 ;
        RECT  0 14.832 0.084 14.856 ;
    END
  END a[44]
  PIN a[45]
    DIRECTION INPUT ;
    USE SIGNAL ;
    PORT
      LAYER M4 ;
        RECT  0 14.976 0.084 15 ;
    END
  END a[45]
  PIN a[46]
    DIRECTION INPUT ;
    USE SIGNAL ;
    PORT
      LAYER M4 ;
        RECT  0 15.12 0.084 15.144 ;
    END
  END a[46]
  PIN a[47]
    DIRECTION INPUT ;
    USE SIGNAL ;
    PORT
      LAYER M4 ;
        RECT  0 15.264 0.084 15.288 ;
    END
  END a[47]
  PIN a[48]
    DIRECTION INPUT ;
    USE SIGNAL ;
    PORT
      LAYER M4 ;
        RECT  0 15.408 0.084 15.432 ;
    END
  END a[48]
  PIN a[49]
    DIRECTION INPUT ;
    USE SIGNAL ;
    PORT
      LAYER M4 ;
        RECT  0 15.552 0.084 15.576 ;
    END
  END a[49]
  PIN a[4]
    DIRECTION INPUT ;
    USE SIGNAL ;
    PORT
      LAYER M4 ;
        RECT  0 42.48 0.084 42.504 ;
    END
  END a[4]
  PIN a[50]
    DIRECTION INPUT ;
    USE SIGNAL ;
    PORT
      LAYER M4 ;
        RECT  0 15.696 0.084 15.72 ;
    END
  END a[50]
  PIN a[51]
    DIRECTION INPUT ;
    USE SIGNAL ;
    PORT
      LAYER M4 ;
        RECT  0 15.84 0.084 15.864 ;
    END
  END a[51]
  PIN a[52]
    DIRECTION INPUT ;
    USE SIGNAL ;
    PORT
      LAYER M4 ;
        RECT  0 15.984 0.084 16.008 ;
    END
  END a[52]
  PIN a[53]
    DIRECTION INPUT ;
    USE SIGNAL ;
    PORT
      LAYER M4 ;
        RECT  0 16.128 0.084 16.152 ;
    END
  END a[53]
  PIN a[54]
    DIRECTION INPUT ;
    USE SIGNAL ;
    PORT
      LAYER M4 ;
        RECT  0 16.272 0.084 16.296 ;
    END
  END a[54]
  PIN a[55]
    DIRECTION INPUT ;
    USE SIGNAL ;
    PORT
      LAYER M4 ;
        RECT  0 16.416 0.084 16.44 ;
    END
  END a[55]
  PIN a[56]
    DIRECTION INPUT ;
    USE SIGNAL ;
    PORT
      LAYER M4 ;
        RECT  0 16.56 0.084 16.584 ;
    END
  END a[56]
  PIN a[57]
    DIRECTION INPUT ;
    USE SIGNAL ;
    PORT
      LAYER M4 ;
        RECT  0 16.704 0.084 16.728 ;
    END
  END a[57]
  PIN a[58]
    DIRECTION INPUT ;
    USE SIGNAL ;
    PORT
      LAYER M4 ;
        RECT  0 16.848 0.084 16.872 ;
    END
  END a[58]
  PIN a[59]
    DIRECTION INPUT ;
    USE SIGNAL ;
    PORT
      LAYER M4 ;
        RECT  0 16.992 0.084 17.016 ;
    END
  END a[59]
  PIN a[5]
    DIRECTION INPUT ;
    USE SIGNAL ;
    PORT
      LAYER M4 ;
        RECT  0 42.624 0.084 42.648 ;
    END
  END a[5]
  PIN a[60]
    DIRECTION INPUT ;
    USE SIGNAL ;
    PORT
      LAYER M4 ;
        RECT  0 17.136 0.084 17.16 ;
    END
  END a[60]
  PIN a[61]
    DIRECTION INPUT ;
    USE SIGNAL ;
    PORT
      LAYER M4 ;
        RECT  0 17.28 0.084 17.304 ;
    END
  END a[61]
  PIN a[62]
    DIRECTION INPUT ;
    USE SIGNAL ;
    PORT
      LAYER M4 ;
        RECT  0 17.424 0.084 17.448 ;
    END
  END a[62]
  PIN a[63]
    DIRECTION INPUT ;
    USE SIGNAL ;
    PORT
      LAYER M4 ;
        RECT  0 17.568 0.084 17.592 ;
    END
  END a[63]
  PIN a[64]
    DIRECTION INPUT ;
    USE SIGNAL ;
    PORT
      LAYER M4 ;
        RECT  0 8.496 0.084 8.52 ;
    END
  END a[64]
  PIN a[65]
    DIRECTION INPUT ;
    USE SIGNAL ;
    PORT
      LAYER M4 ;
        RECT  0 8.64 0.084 8.664 ;
    END
  END a[65]
  PIN a[66]
    DIRECTION INPUT ;
    USE SIGNAL ;
    PORT
      LAYER M4 ;
        RECT  0 8.784 0.084 8.808 ;
    END
  END a[66]
  PIN a[67]
    DIRECTION INPUT ;
    USE SIGNAL ;
    PORT
      LAYER M4 ;
        RECT  0 8.928 0.084 8.952 ;
    END
  END a[67]
  PIN a[68]
    DIRECTION INPUT ;
    USE SIGNAL ;
    PORT
      LAYER M4 ;
        RECT  0 9.072 0.084 9.096 ;
    END
  END a[68]
  PIN a[69]
    DIRECTION INPUT ;
    USE SIGNAL ;
    PORT
      LAYER M4 ;
        RECT  0 9.216 0.084 9.24 ;
    END
  END a[69]
  PIN a[6]
    DIRECTION INPUT ;
    USE SIGNAL ;
    PORT
      LAYER M4 ;
        RECT  0 42.768 0.084 42.792 ;
    END
  END a[6]
  PIN a[70]
    DIRECTION INPUT ;
    USE SIGNAL ;
    PORT
      LAYER M4 ;
        RECT  0 9.36 0.084 9.384 ;
    END
  END a[70]
  PIN a[71]
    DIRECTION INPUT ;
    USE SIGNAL ;
    PORT
      LAYER M4 ;
        RECT  0 9.504 0.084 9.528 ;
    END
  END a[71]
  PIN a[72]
    DIRECTION INPUT ;
    USE SIGNAL ;
    PORT
      LAYER M4 ;
        RECT  0 9.648 0.084 9.672 ;
    END
  END a[72]
  PIN a[73]
    DIRECTION INPUT ;
    USE SIGNAL ;
    PORT
      LAYER M4 ;
        RECT  0 9.792 0.084 9.816 ;
    END
  END a[73]
  PIN a[74]
    DIRECTION INPUT ;
    USE SIGNAL ;
    PORT
      LAYER M4 ;
        RECT  0 9.936 0.084 9.96 ;
    END
  END a[74]
  PIN a[75]
    DIRECTION INPUT ;
    USE SIGNAL ;
    PORT
      LAYER M4 ;
        RECT  0 10.08 0.084 10.104 ;
    END
  END a[75]
  PIN a[76]
    DIRECTION INPUT ;
    USE SIGNAL ;
    PORT
      LAYER M4 ;
        RECT  0 10.224 0.084 10.248 ;
    END
  END a[76]
  PIN a[77]
    DIRECTION INPUT ;
    USE SIGNAL ;
    PORT
      LAYER M4 ;
        RECT  0 10.368 0.084 10.392 ;
    END
  END a[77]
  PIN a[78]
    DIRECTION INPUT ;
    USE SIGNAL ;
    PORT
      LAYER M4 ;
        RECT  0 10.512 0.084 10.536 ;
    END
  END a[78]
  PIN a[79]
    DIRECTION INPUT ;
    USE SIGNAL ;
    PORT
      LAYER M4 ;
        RECT  0 10.656 0.084 10.68 ;
    END
  END a[79]
  PIN a[7]
    DIRECTION INPUT ;
    USE SIGNAL ;
    PORT
      LAYER M4 ;
        RECT  0 42.912 0.084 42.936 ;
    END
  END a[7]
  PIN a[80]
    DIRECTION INPUT ;
    USE SIGNAL ;
    PORT
      LAYER M4 ;
        RECT  0 10.8 0.084 10.824 ;
    END
  END a[80]
  PIN a[81]
    DIRECTION INPUT ;
    USE SIGNAL ;
    PORT
      LAYER M4 ;
        RECT  0 10.944 0.084 10.968 ;
    END
  END a[81]
  PIN a[82]
    DIRECTION INPUT ;
    USE SIGNAL ;
    PORT
      LAYER M4 ;
        RECT  0 11.088 0.084 11.112 ;
    END
  END a[82]
  PIN a[83]
    DIRECTION INPUT ;
    USE SIGNAL ;
    PORT
      LAYER M4 ;
        RECT  0 11.232 0.084 11.256 ;
    END
  END a[83]
  PIN a[84]
    DIRECTION INPUT ;
    USE SIGNAL ;
    PORT
      LAYER M4 ;
        RECT  0 11.376 0.084 11.4 ;
    END
  END a[84]
  PIN a[85]
    DIRECTION INPUT ;
    USE SIGNAL ;
    PORT
      LAYER M4 ;
        RECT  0 11.52 0.084 11.544 ;
    END
  END a[85]
  PIN a[86]
    DIRECTION INPUT ;
    USE SIGNAL ;
    PORT
      LAYER M4 ;
        RECT  0 11.664 0.084 11.688 ;
    END
  END a[86]
  PIN a[87]
    DIRECTION INPUT ;
    USE SIGNAL ;
    PORT
      LAYER M4 ;
        RECT  0 11.808 0.084 11.832 ;
    END
  END a[87]
  PIN a[88]
    DIRECTION INPUT ;
    USE SIGNAL ;
    PORT
      LAYER M4 ;
        RECT  0 11.952 0.084 11.976 ;
    END
  END a[88]
  PIN a[89]
    DIRECTION INPUT ;
    USE SIGNAL ;
    PORT
      LAYER M4 ;
        RECT  0 12.096 0.084 12.12 ;
    END
  END a[89]
  PIN a[8]
    DIRECTION INPUT ;
    USE SIGNAL ;
    PORT
      LAYER M4 ;
        RECT  0 43.056 0.084 43.08 ;
    END
  END a[8]
  PIN a[90]
    DIRECTION INPUT ;
    USE SIGNAL ;
    PORT
      LAYER M4 ;
        RECT  0 12.24 0.084 12.264 ;
    END
  END a[90]
  PIN a[91]
    DIRECTION INPUT ;
    USE SIGNAL ;
    PORT
      LAYER M4 ;
        RECT  0 12.384 0.084 12.408 ;
    END
  END a[91]
  PIN a[92]
    DIRECTION INPUT ;
    USE SIGNAL ;
    PORT
      LAYER M4 ;
        RECT  0 12.528 0.084 12.552 ;
    END
  END a[92]
  PIN a[93]
    DIRECTION INPUT ;
    USE SIGNAL ;
    PORT
      LAYER M4 ;
        RECT  0 12.672 0.084 12.696 ;
    END
  END a[93]
  PIN a[94]
    DIRECTION INPUT ;
    USE SIGNAL ;
    PORT
      LAYER M4 ;
        RECT  0 12.816 0.084 12.84 ;
    END
  END a[94]
  PIN a[95]
    DIRECTION INPUT ;
    USE SIGNAL ;
    PORT
      LAYER M4 ;
        RECT  0 12.96 0.084 12.984 ;
    END
  END a[95]
  PIN a[96]
    DIRECTION INPUT ;
    USE SIGNAL ;
    PORT
      LAYER M4 ;
        RECT  0 32.688 0.084 32.712 ;
    END
  END a[96]
  PIN a[97]
    DIRECTION INPUT ;
    USE SIGNAL ;
    PORT
      LAYER M4 ;
        RECT  0 32.832 0.084 32.856 ;
    END
  END a[97]
  PIN a[98]
    DIRECTION INPUT ;
    USE SIGNAL ;
    PORT
      LAYER M4 ;
        RECT  0 32.976 0.084 33 ;
    END
  END a[98]
  PIN a[99]
    DIRECTION INPUT ;
    USE SIGNAL ;
    PORT
      LAYER M4 ;
        RECT  0 33.12 0.084 33.144 ;
    END
  END a[99]
  PIN a[9]
    DIRECTION INPUT ;
    USE SIGNAL ;
    PORT
      LAYER M4 ;
        RECT  0 43.2 0.084 43.224 ;
    END
  END a[9]
  PIN b[0]
    DIRECTION OUTPUT ;
    USE SIGNAL ;
    PORT
      LAYER M4 ;
        RECT  25.836 43.344 25.92 43.368 ;
    END
  END b[0]
  PIN b[100]
    DIRECTION OUTPUT ;
    USE SIGNAL ;
    PORT
      LAYER M4 ;
        RECT  25.836 39.312 25.92 39.336 ;
    END
  END b[100]
  PIN b[101]
    DIRECTION OUTPUT ;
    USE SIGNAL ;
    PORT
      LAYER M4 ;
        RECT  25.836 39.456 25.92 39.48 ;
    END
  END b[101]
  PIN b[102]
    DIRECTION OUTPUT ;
    USE SIGNAL ;
    PORT
      LAYER M4 ;
        RECT  25.836 39.6 25.92 39.624 ;
    END
  END b[102]
  PIN b[103]
    DIRECTION OUTPUT ;
    USE SIGNAL ;
    PORT
      LAYER M4 ;
        RECT  25.836 39.744 25.92 39.768 ;
    END
  END b[103]
  PIN b[104]
    DIRECTION OUTPUT ;
    USE SIGNAL ;
    PORT
      LAYER M4 ;
        RECT  25.836 39.888 25.92 39.912 ;
    END
  END b[104]
  PIN b[105]
    DIRECTION OUTPUT ;
    USE SIGNAL ;
    PORT
      LAYER M4 ;
        RECT  25.836 40.032 25.92 40.056 ;
    END
  END b[105]
  PIN b[106]
    DIRECTION OUTPUT ;
    USE SIGNAL ;
    PORT
      LAYER M4 ;
        RECT  25.836 40.176 25.92 40.2 ;
    END
  END b[106]
  PIN b[107]
    DIRECTION OUTPUT ;
    USE SIGNAL ;
    PORT
      LAYER M4 ;
        RECT  25.836 40.32 25.92 40.344 ;
    END
  END b[107]
  PIN b[108]
    DIRECTION OUTPUT ;
    USE SIGNAL ;
    PORT
      LAYER M4 ;
        RECT  25.836 40.464 25.92 40.488 ;
    END
  END b[108]
  PIN b[109]
    DIRECTION OUTPUT ;
    USE SIGNAL ;
    PORT
      LAYER M4 ;
        RECT  25.836 40.608 25.92 40.632 ;
    END
  END b[109]
  PIN b[10]
    DIRECTION OUTPUT ;
    USE SIGNAL ;
    PORT
      LAYER M4 ;
        RECT  25.836 44.784 25.92 44.808 ;
    END
  END b[10]
  PIN b[110]
    DIRECTION OUTPUT ;
    USE SIGNAL ;
    PORT
      LAYER M4 ;
        RECT  25.836 40.752 25.92 40.776 ;
    END
  END b[110]
  PIN b[111]
    DIRECTION OUTPUT ;
    USE SIGNAL ;
    PORT
      LAYER M4 ;
        RECT  25.836 40.896 25.92 40.92 ;
    END
  END b[111]
  PIN b[112]
    DIRECTION OUTPUT ;
    USE SIGNAL ;
    PORT
      LAYER M4 ;
        RECT  25.836 41.04 25.92 41.064 ;
    END
  END b[112]
  PIN b[113]
    DIRECTION OUTPUT ;
    USE SIGNAL ;
    PORT
      LAYER M4 ;
        RECT  25.836 41.184 25.92 41.208 ;
    END
  END b[113]
  PIN b[114]
    DIRECTION OUTPUT ;
    USE SIGNAL ;
    PORT
      LAYER M4 ;
        RECT  25.836 41.328 25.92 41.352 ;
    END
  END b[114]
  PIN b[115]
    DIRECTION OUTPUT ;
    USE SIGNAL ;
    PORT
      LAYER M4 ;
        RECT  25.836 41.472 25.92 41.496 ;
    END
  END b[115]
  PIN b[116]
    DIRECTION OUTPUT ;
    USE SIGNAL ;
    PORT
      LAYER M4 ;
        RECT  25.836 41.616 25.92 41.64 ;
    END
  END b[116]
  PIN b[117]
    DIRECTION OUTPUT ;
    USE SIGNAL ;
    PORT
      LAYER M4 ;
        RECT  25.836 41.76 25.92 41.784 ;
    END
  END b[117]
  PIN b[118]
    DIRECTION OUTPUT ;
    USE SIGNAL ;
    PORT
      LAYER M4 ;
        RECT  25.836 41.904 25.92 41.928 ;
    END
  END b[118]
  PIN b[119]
    DIRECTION OUTPUT ;
    USE SIGNAL ;
    PORT
      LAYER M4 ;
        RECT  25.836 42.048 25.92 42.072 ;
    END
  END b[119]
  PIN b[11]
    DIRECTION OUTPUT ;
    USE SIGNAL ;
    PORT
      LAYER M4 ;
        RECT  25.836 44.928 25.92 44.952 ;
    END
  END b[11]
  PIN b[120]
    DIRECTION OUTPUT ;
    USE SIGNAL ;
    PORT
      LAYER M4 ;
        RECT  25.836 42.192 25.92 42.216 ;
    END
  END b[120]
  PIN b[121]
    DIRECTION OUTPUT ;
    USE SIGNAL ;
    PORT
      LAYER M4 ;
        RECT  25.836 42.336 25.92 42.36 ;
    END
  END b[121]
  PIN b[122]
    DIRECTION OUTPUT ;
    USE SIGNAL ;
    PORT
      LAYER M4 ;
        RECT  25.836 42.48 25.92 42.504 ;
    END
  END b[122]
  PIN b[123]
    DIRECTION OUTPUT ;
    USE SIGNAL ;
    PORT
      LAYER M4 ;
        RECT  25.836 42.624 25.92 42.648 ;
    END
  END b[123]
  PIN b[124]
    DIRECTION OUTPUT ;
    USE SIGNAL ;
    PORT
      LAYER M4 ;
        RECT  25.836 42.768 25.92 42.792 ;
    END
  END b[124]
  PIN b[125]
    DIRECTION OUTPUT ;
    USE SIGNAL ;
    PORT
      LAYER M4 ;
        RECT  25.836 42.912 25.92 42.936 ;
    END
  END b[125]
  PIN b[126]
    DIRECTION OUTPUT ;
    USE SIGNAL ;
    PORT
      LAYER M4 ;
        RECT  25.836 43.056 25.92 43.08 ;
    END
  END b[126]
  PIN b[127]
    DIRECTION OUTPUT ;
    USE SIGNAL ;
    PORT
      LAYER M4 ;
        RECT  25.836 43.2 25.92 43.224 ;
    END
  END b[127]
  PIN b[128]
    DIRECTION OUTPUT ;
    USE SIGNAL ;
    PORT
      LAYER M4 ;
        RECT  25.836 19.152 25.92 19.176 ;
    END
  END b[128]
  PIN b[129]
    DIRECTION OUTPUT ;
    USE SIGNAL ;
    PORT
      LAYER M4 ;
        RECT  25.836 19.296 25.92 19.32 ;
    END
  END b[129]
  PIN b[12]
    DIRECTION OUTPUT ;
    USE SIGNAL ;
    PORT
      LAYER M4 ;
        RECT  25.836 45.072 25.92 45.096 ;
    END
  END b[12]
  PIN b[130]
    DIRECTION OUTPUT ;
    USE SIGNAL ;
    PORT
      LAYER M4 ;
        RECT  25.836 19.44 25.92 19.464 ;
    END
  END b[130]
  PIN b[131]
    DIRECTION OUTPUT ;
    USE SIGNAL ;
    PORT
      LAYER M4 ;
        RECT  25.836 19.584 25.92 19.608 ;
    END
  END b[131]
  PIN b[132]
    DIRECTION OUTPUT ;
    USE SIGNAL ;
    PORT
      LAYER M4 ;
        RECT  25.836 19.728 25.92 19.752 ;
    END
  END b[132]
  PIN b[133]
    DIRECTION OUTPUT ;
    USE SIGNAL ;
    PORT
      LAYER M4 ;
        RECT  25.836 19.872 25.92 19.896 ;
    END
  END b[133]
  PIN b[134]
    DIRECTION OUTPUT ;
    USE SIGNAL ;
    PORT
      LAYER M4 ;
        RECT  25.836 20.016 25.92 20.04 ;
    END
  END b[134]
  PIN b[135]
    DIRECTION OUTPUT ;
    USE SIGNAL ;
    PORT
      LAYER M4 ;
        RECT  25.836 20.16 25.92 20.184 ;
    END
  END b[135]
  PIN b[136]
    DIRECTION OUTPUT ;
    USE SIGNAL ;
    PORT
      LAYER M4 ;
        RECT  25.836 20.304 25.92 20.328 ;
    END
  END b[136]
  PIN b[137]
    DIRECTION OUTPUT ;
    USE SIGNAL ;
    PORT
      LAYER M4 ;
        RECT  25.836 20.448 25.92 20.472 ;
    END
  END b[137]
  PIN b[138]
    DIRECTION OUTPUT ;
    USE SIGNAL ;
    PORT
      LAYER M4 ;
        RECT  25.836 20.592 25.92 20.616 ;
    END
  END b[138]
  PIN b[139]
    DIRECTION OUTPUT ;
    USE SIGNAL ;
    PORT
      LAYER M4 ;
        RECT  25.836 20.736 25.92 20.76 ;
    END
  END b[139]
  PIN b[13]
    DIRECTION OUTPUT ;
    USE SIGNAL ;
    PORT
      LAYER M4 ;
        RECT  25.836 45.216 25.92 45.24 ;
    END
  END b[13]
  PIN b[140]
    DIRECTION OUTPUT ;
    USE SIGNAL ;
    PORT
      LAYER M4 ;
        RECT  25.836 20.88 25.92 20.904 ;
    END
  END b[140]
  PIN b[141]
    DIRECTION OUTPUT ;
    USE SIGNAL ;
    PORT
      LAYER M4 ;
        RECT  25.836 21.024 25.92 21.048 ;
    END
  END b[141]
  PIN b[142]
    DIRECTION OUTPUT ;
    USE SIGNAL ;
    PORT
      LAYER M4 ;
        RECT  25.836 21.168 25.92 21.192 ;
    END
  END b[142]
  PIN b[143]
    DIRECTION OUTPUT ;
    USE SIGNAL ;
    PORT
      LAYER M4 ;
        RECT  25.836 21.312 25.92 21.336 ;
    END
  END b[143]
  PIN b[144]
    DIRECTION OUTPUT ;
    USE SIGNAL ;
    PORT
      LAYER M4 ;
        RECT  25.836 21.456 25.92 21.48 ;
    END
  END b[144]
  PIN b[145]
    DIRECTION OUTPUT ;
    USE SIGNAL ;
    PORT
      LAYER M4 ;
        RECT  25.836 21.6 25.92 21.624 ;
    END
  END b[145]
  PIN b[146]
    DIRECTION OUTPUT ;
    USE SIGNAL ;
    PORT
      LAYER M4 ;
        RECT  25.836 21.744 25.92 21.768 ;
    END
  END b[146]
  PIN b[147]
    DIRECTION OUTPUT ;
    USE SIGNAL ;
    PORT
      LAYER M4 ;
        RECT  25.836 21.888 25.92 21.912 ;
    END
  END b[147]
  PIN b[148]
    DIRECTION OUTPUT ;
    USE SIGNAL ;
    PORT
      LAYER M4 ;
        RECT  25.836 22.032 25.92 22.056 ;
    END
  END b[148]
  PIN b[149]
    DIRECTION OUTPUT ;
    USE SIGNAL ;
    PORT
      LAYER M4 ;
        RECT  25.836 22.176 25.92 22.2 ;
    END
  END b[149]
  PIN b[14]
    DIRECTION OUTPUT ;
    USE SIGNAL ;
    PORT
      LAYER M4 ;
        RECT  25.836 45.36 25.92 45.384 ;
    END
  END b[14]
  PIN b[150]
    DIRECTION OUTPUT ;
    USE SIGNAL ;
    PORT
      LAYER M4 ;
        RECT  25.836 22.32 25.92 22.344 ;
    END
  END b[150]
  PIN b[151]
    DIRECTION OUTPUT ;
    USE SIGNAL ;
    PORT
      LAYER M4 ;
        RECT  25.836 22.464 25.92 22.488 ;
    END
  END b[151]
  PIN b[152]
    DIRECTION OUTPUT ;
    USE SIGNAL ;
    PORT
      LAYER M4 ;
        RECT  25.836 22.608 25.92 22.632 ;
    END
  END b[152]
  PIN b[153]
    DIRECTION OUTPUT ;
    USE SIGNAL ;
    PORT
      LAYER M4 ;
        RECT  25.836 22.752 25.92 22.776 ;
    END
  END b[153]
  PIN b[154]
    DIRECTION OUTPUT ;
    USE SIGNAL ;
    PORT
      LAYER M4 ;
        RECT  25.836 22.896 25.92 22.92 ;
    END
  END b[154]
  PIN b[155]
    DIRECTION OUTPUT ;
    USE SIGNAL ;
    PORT
      LAYER M4 ;
        RECT  25.836 23.04 25.92 23.064 ;
    END
  END b[155]
  PIN b[156]
    DIRECTION OUTPUT ;
    USE SIGNAL ;
    PORT
      LAYER M4 ;
        RECT  25.836 23.184 25.92 23.208 ;
    END
  END b[156]
  PIN b[157]
    DIRECTION OUTPUT ;
    USE SIGNAL ;
    PORT
      LAYER M4 ;
        RECT  25.836 23.328 25.92 23.352 ;
    END
  END b[157]
  PIN b[158]
    DIRECTION OUTPUT ;
    USE SIGNAL ;
    PORT
      LAYER M4 ;
        RECT  25.836 23.472 25.92 23.496 ;
    END
  END b[158]
  PIN b[159]
    DIRECTION OUTPUT ;
    USE SIGNAL ;
    PORT
      LAYER M4 ;
        RECT  25.836 23.616 25.92 23.64 ;
    END
  END b[159]
  PIN b[15]
    DIRECTION OUTPUT ;
    USE SIGNAL ;
    PORT
      LAYER M4 ;
        RECT  25.836 45.504 25.92 45.528 ;
    END
  END b[15]
  PIN b[160]
    DIRECTION OUTPUT ;
    USE SIGNAL ;
    PORT
      LAYER M4 ;
        RECT  25.836 29.52 25.92 29.544 ;
    END
  END b[160]
  PIN b[161]
    DIRECTION OUTPUT ;
    USE SIGNAL ;
    PORT
      LAYER M4 ;
        RECT  25.836 29.664 25.92 29.688 ;
    END
  END b[161]
  PIN b[162]
    DIRECTION OUTPUT ;
    USE SIGNAL ;
    PORT
      LAYER M4 ;
        RECT  25.836 29.808 25.92 29.832 ;
    END
  END b[162]
  PIN b[163]
    DIRECTION OUTPUT ;
    USE SIGNAL ;
    PORT
      LAYER M4 ;
        RECT  25.836 29.952 25.92 29.976 ;
    END
  END b[163]
  PIN b[164]
    DIRECTION OUTPUT ;
    USE SIGNAL ;
    PORT
      LAYER M4 ;
        RECT  25.836 30.096 25.92 30.12 ;
    END
  END b[164]
  PIN b[165]
    DIRECTION OUTPUT ;
    USE SIGNAL ;
    PORT
      LAYER M4 ;
        RECT  25.836 30.24 25.92 30.264 ;
    END
  END b[165]
  PIN b[166]
    DIRECTION OUTPUT ;
    USE SIGNAL ;
    PORT
      LAYER M4 ;
        RECT  25.836 30.384 25.92 30.408 ;
    END
  END b[166]
  PIN b[167]
    DIRECTION OUTPUT ;
    USE SIGNAL ;
    PORT
      LAYER M4 ;
        RECT  25.836 30.528 25.92 30.552 ;
    END
  END b[167]
  PIN b[168]
    DIRECTION OUTPUT ;
    USE SIGNAL ;
    PORT
      LAYER M4 ;
        RECT  25.836 30.672 25.92 30.696 ;
    END
  END b[168]
  PIN b[169]
    DIRECTION OUTPUT ;
    USE SIGNAL ;
    PORT
      LAYER M4 ;
        RECT  25.836 30.816 25.92 30.84 ;
    END
  END b[169]
  PIN b[16]
    DIRECTION OUTPUT ;
    USE SIGNAL ;
    PORT
      LAYER M4 ;
        RECT  25.836 45.648 25.92 45.672 ;
    END
  END b[16]
  PIN b[170]
    DIRECTION OUTPUT ;
    USE SIGNAL ;
    PORT
      LAYER M4 ;
        RECT  25.836 30.96 25.92 30.984 ;
    END
  END b[170]
  PIN b[171]
    DIRECTION OUTPUT ;
    USE SIGNAL ;
    PORT
      LAYER M4 ;
        RECT  25.836 31.104 25.92 31.128 ;
    END
  END b[171]
  PIN b[172]
    DIRECTION OUTPUT ;
    USE SIGNAL ;
    PORT
      LAYER M4 ;
        RECT  25.836 31.248 25.92 31.272 ;
    END
  END b[172]
  PIN b[173]
    DIRECTION OUTPUT ;
    USE SIGNAL ;
    PORT
      LAYER M4 ;
        RECT  25.836 31.392 25.92 31.416 ;
    END
  END b[173]
  PIN b[174]
    DIRECTION OUTPUT ;
    USE SIGNAL ;
    PORT
      LAYER M4 ;
        RECT  25.836 31.536 25.92 31.56 ;
    END
  END b[174]
  PIN b[175]
    DIRECTION OUTPUT ;
    USE SIGNAL ;
    PORT
      LAYER M4 ;
        RECT  25.836 31.68 25.92 31.704 ;
    END
  END b[175]
  PIN b[176]
    DIRECTION OUTPUT ;
    USE SIGNAL ;
    PORT
      LAYER M4 ;
        RECT  25.836 31.824 25.92 31.848 ;
    END
  END b[176]
  PIN b[177]
    DIRECTION OUTPUT ;
    USE SIGNAL ;
    PORT
      LAYER M4 ;
        RECT  25.836 31.968 25.92 31.992 ;
    END
  END b[177]
  PIN b[178]
    DIRECTION OUTPUT ;
    USE SIGNAL ;
    PORT
      LAYER M4 ;
        RECT  25.836 32.112 25.92 32.136 ;
    END
  END b[178]
  PIN b[179]
    DIRECTION OUTPUT ;
    USE SIGNAL ;
    PORT
      LAYER M4 ;
        RECT  25.836 32.256 25.92 32.28 ;
    END
  END b[179]
  PIN b[17]
    DIRECTION OUTPUT ;
    USE SIGNAL ;
    PORT
      LAYER M4 ;
        RECT  25.836 45.792 25.92 45.816 ;
    END
  END b[17]
  PIN b[180]
    DIRECTION OUTPUT ;
    USE SIGNAL ;
    PORT
      LAYER M4 ;
        RECT  25.836 32.4 25.92 32.424 ;
    END
  END b[180]
  PIN b[181]
    DIRECTION OUTPUT ;
    USE SIGNAL ;
    PORT
      LAYER M4 ;
        RECT  25.836 32.544 25.92 32.568 ;
    END
  END b[181]
  PIN b[182]
    DIRECTION OUTPUT ;
    USE SIGNAL ;
    PORT
      LAYER M4 ;
        RECT  25.836 32.688 25.92 32.712 ;
    END
  END b[182]
  PIN b[183]
    DIRECTION OUTPUT ;
    USE SIGNAL ;
    PORT
      LAYER M4 ;
        RECT  25.836 32.832 25.92 32.856 ;
    END
  END b[183]
  PIN b[184]
    DIRECTION OUTPUT ;
    USE SIGNAL ;
    PORT
      LAYER M4 ;
        RECT  25.836 32.976 25.92 33 ;
    END
  END b[184]
  PIN b[185]
    DIRECTION OUTPUT ;
    USE SIGNAL ;
    PORT
      LAYER M4 ;
        RECT  25.836 33.12 25.92 33.144 ;
    END
  END b[185]
  PIN b[186]
    DIRECTION OUTPUT ;
    USE SIGNAL ;
    PORT
      LAYER M4 ;
        RECT  25.836 33.264 25.92 33.288 ;
    END
  END b[186]
  PIN b[187]
    DIRECTION OUTPUT ;
    USE SIGNAL ;
    PORT
      LAYER M4 ;
        RECT  25.836 33.408 25.92 33.432 ;
    END
  END b[187]
  PIN b[188]
    DIRECTION OUTPUT ;
    USE SIGNAL ;
    PORT
      LAYER M4 ;
        RECT  25.836 33.552 25.92 33.576 ;
    END
  END b[188]
  PIN b[189]
    DIRECTION OUTPUT ;
    USE SIGNAL ;
    PORT
      LAYER M4 ;
        RECT  25.836 33.696 25.92 33.72 ;
    END
  END b[189]
  PIN b[18]
    DIRECTION OUTPUT ;
    USE SIGNAL ;
    PORT
      LAYER M4 ;
        RECT  25.836 45.936 25.92 45.96 ;
    END
  END b[18]
  PIN b[190]
    DIRECTION OUTPUT ;
    USE SIGNAL ;
    PORT
      LAYER M4 ;
        RECT  25.836 33.84 25.92 33.864 ;
    END
  END b[190]
  PIN b[191]
    DIRECTION OUTPUT ;
    USE SIGNAL ;
    PORT
      LAYER M4 ;
        RECT  25.836 33.984 25.92 34.008 ;
    END
  END b[191]
  PIN b[192]
    DIRECTION OUTPUT ;
    USE SIGNAL ;
    PORT
      LAYER M4 ;
        RECT  25.836 34.128 25.92 34.152 ;
    END
  END b[192]
  PIN b[193]
    DIRECTION OUTPUT ;
    USE SIGNAL ;
    PORT
      LAYER M4 ;
        RECT  25.836 34.272 25.92 34.296 ;
    END
  END b[193]
  PIN b[194]
    DIRECTION OUTPUT ;
    USE SIGNAL ;
    PORT
      LAYER M4 ;
        RECT  25.836 34.416 25.92 34.44 ;
    END
  END b[194]
  PIN b[195]
    DIRECTION OUTPUT ;
    USE SIGNAL ;
    PORT
      LAYER M4 ;
        RECT  25.836 34.56 25.92 34.584 ;
    END
  END b[195]
  PIN b[196]
    DIRECTION OUTPUT ;
    USE SIGNAL ;
    PORT
      LAYER M4 ;
        RECT  25.836 34.704 25.92 34.728 ;
    END
  END b[196]
  PIN b[197]
    DIRECTION OUTPUT ;
    USE SIGNAL ;
    PORT
      LAYER M4 ;
        RECT  25.836 34.848 25.92 34.872 ;
    END
  END b[197]
  PIN b[198]
    DIRECTION OUTPUT ;
    USE SIGNAL ;
    PORT
      LAYER M4 ;
        RECT  25.836 34.992 25.92 35.016 ;
    END
  END b[198]
  PIN b[199]
    DIRECTION OUTPUT ;
    USE SIGNAL ;
    PORT
      LAYER M4 ;
        RECT  25.836 35.136 25.92 35.16 ;
    END
  END b[199]
  PIN b[19]
    DIRECTION OUTPUT ;
    USE SIGNAL ;
    PORT
      LAYER M4 ;
        RECT  25.836 46.08 25.92 46.104 ;
    END
  END b[19]
  PIN b[1]
    DIRECTION OUTPUT ;
    USE SIGNAL ;
    PORT
      LAYER M4 ;
        RECT  25.836 43.488 25.92 43.512 ;
    END
  END b[1]
  PIN b[200]
    DIRECTION OUTPUT ;
    USE SIGNAL ;
    PORT
      LAYER M4 ;
        RECT  25.836 35.28 25.92 35.304 ;
    END
  END b[200]
  PIN b[201]
    DIRECTION OUTPUT ;
    USE SIGNAL ;
    PORT
      LAYER M4 ;
        RECT  25.836 35.424 25.92 35.448 ;
    END
  END b[201]
  PIN b[202]
    DIRECTION OUTPUT ;
    USE SIGNAL ;
    PORT
      LAYER M4 ;
        RECT  25.836 35.568 25.92 35.592 ;
    END
  END b[202]
  PIN b[203]
    DIRECTION OUTPUT ;
    USE SIGNAL ;
    PORT
      LAYER M4 ;
        RECT  25.836 35.712 25.92 35.736 ;
    END
  END b[203]
  PIN b[204]
    DIRECTION OUTPUT ;
    USE SIGNAL ;
    PORT
      LAYER M4 ;
        RECT  25.836 35.856 25.92 35.88 ;
    END
  END b[204]
  PIN b[205]
    DIRECTION OUTPUT ;
    USE SIGNAL ;
    PORT
      LAYER M4 ;
        RECT  25.836 36 25.92 36.024 ;
    END
  END b[205]
  PIN b[206]
    DIRECTION OUTPUT ;
    USE SIGNAL ;
    PORT
      LAYER M4 ;
        RECT  25.836 36.144 25.92 36.168 ;
    END
  END b[206]
  PIN b[207]
    DIRECTION OUTPUT ;
    USE SIGNAL ;
    PORT
      LAYER M4 ;
        RECT  25.836 36.288 25.92 36.312 ;
    END
  END b[207]
  PIN b[208]
    DIRECTION OUTPUT ;
    USE SIGNAL ;
    PORT
      LAYER M4 ;
        RECT  25.836 36.432 25.92 36.456 ;
    END
  END b[208]
  PIN b[209]
    DIRECTION OUTPUT ;
    USE SIGNAL ;
    PORT
      LAYER M4 ;
        RECT  25.836 36.576 25.92 36.6 ;
    END
  END b[209]
  PIN b[20]
    DIRECTION OUTPUT ;
    USE SIGNAL ;
    PORT
      LAYER M4 ;
        RECT  25.836 46.224 25.92 46.248 ;
    END
  END b[20]
  PIN b[210]
    DIRECTION OUTPUT ;
    USE SIGNAL ;
    PORT
      LAYER M4 ;
        RECT  25.836 36.72 25.92 36.744 ;
    END
  END b[210]
  PIN b[211]
    DIRECTION OUTPUT ;
    USE SIGNAL ;
    PORT
      LAYER M4 ;
        RECT  25.836 36.864 25.92 36.888 ;
    END
  END b[211]
  PIN b[212]
    DIRECTION OUTPUT ;
    USE SIGNAL ;
    PORT
      LAYER M4 ;
        RECT  25.836 37.008 25.92 37.032 ;
    END
  END b[212]
  PIN b[213]
    DIRECTION OUTPUT ;
    USE SIGNAL ;
    PORT
      LAYER M4 ;
        RECT  25.836 37.152 25.92 37.176 ;
    END
  END b[213]
  PIN b[214]
    DIRECTION OUTPUT ;
    USE SIGNAL ;
    PORT
      LAYER M4 ;
        RECT  25.836 37.296 25.92 37.32 ;
    END
  END b[214]
  PIN b[215]
    DIRECTION OUTPUT ;
    USE SIGNAL ;
    PORT
      LAYER M4 ;
        RECT  25.836 37.44 25.92 37.464 ;
    END
  END b[215]
  PIN b[216]
    DIRECTION OUTPUT ;
    USE SIGNAL ;
    PORT
      LAYER M4 ;
        RECT  25.836 37.584 25.92 37.608 ;
    END
  END b[216]
  PIN b[217]
    DIRECTION OUTPUT ;
    USE SIGNAL ;
    PORT
      LAYER M4 ;
        RECT  25.836 37.728 25.92 37.752 ;
    END
  END b[217]
  PIN b[218]
    DIRECTION OUTPUT ;
    USE SIGNAL ;
    PORT
      LAYER M4 ;
        RECT  25.836 37.872 25.92 37.896 ;
    END
  END b[218]
  PIN b[219]
    DIRECTION OUTPUT ;
    USE SIGNAL ;
    PORT
      LAYER M4 ;
        RECT  25.836 38.016 25.92 38.04 ;
    END
  END b[219]
  PIN b[21]
    DIRECTION OUTPUT ;
    USE SIGNAL ;
    PORT
      LAYER M4 ;
        RECT  25.836 46.368 25.92 46.392 ;
    END
  END b[21]
  PIN b[220]
    DIRECTION OUTPUT ;
    USE SIGNAL ;
    PORT
      LAYER M4 ;
        RECT  25.836 38.16 25.92 38.184 ;
    END
  END b[220]
  PIN b[221]
    DIRECTION OUTPUT ;
    USE SIGNAL ;
    PORT
      LAYER M4 ;
        RECT  25.836 38.304 25.92 38.328 ;
    END
  END b[221]
  PIN b[222]
    DIRECTION OUTPUT ;
    USE SIGNAL ;
    PORT
      LAYER M4 ;
        RECT  25.836 38.448 25.92 38.472 ;
    END
  END b[222]
  PIN b[223]
    DIRECTION OUTPUT ;
    USE SIGNAL ;
    PORT
      LAYER M4 ;
        RECT  25.836 38.592 25.92 38.616 ;
    END
  END b[223]
  PIN b[224]
    DIRECTION OUTPUT ;
    USE SIGNAL ;
    PORT
      LAYER M4 ;
        RECT  25.836 9.936 25.92 9.96 ;
    END
  END b[224]
  PIN b[225]
    DIRECTION OUTPUT ;
    USE SIGNAL ;
    PORT
      LAYER M4 ;
        RECT  25.836 10.08 25.92 10.104 ;
    END
  END b[225]
  PIN b[226]
    DIRECTION OUTPUT ;
    USE SIGNAL ;
    PORT
      LAYER M4 ;
        RECT  25.836 10.224 25.92 10.248 ;
    END
  END b[226]
  PIN b[227]
    DIRECTION OUTPUT ;
    USE SIGNAL ;
    PORT
      LAYER M4 ;
        RECT  25.836 10.368 25.92 10.392 ;
    END
  END b[227]
  PIN b[228]
    DIRECTION OUTPUT ;
    USE SIGNAL ;
    PORT
      LAYER M4 ;
        RECT  25.836 10.512 25.92 10.536 ;
    END
  END b[228]
  PIN b[229]
    DIRECTION OUTPUT ;
    USE SIGNAL ;
    PORT
      LAYER M4 ;
        RECT  25.836 10.656 25.92 10.68 ;
    END
  END b[229]
  PIN b[22]
    DIRECTION OUTPUT ;
    USE SIGNAL ;
    PORT
      LAYER M4 ;
        RECT  25.836 46.512 25.92 46.536 ;
    END
  END b[22]
  PIN b[230]
    DIRECTION OUTPUT ;
    USE SIGNAL ;
    PORT
      LAYER M4 ;
        RECT  25.836 10.8 25.92 10.824 ;
    END
  END b[230]
  PIN b[231]
    DIRECTION OUTPUT ;
    USE SIGNAL ;
    PORT
      LAYER M4 ;
        RECT  25.836 10.944 25.92 10.968 ;
    END
  END b[231]
  PIN b[232]
    DIRECTION OUTPUT ;
    USE SIGNAL ;
    PORT
      LAYER M4 ;
        RECT  25.836 11.088 25.92 11.112 ;
    END
  END b[232]
  PIN b[233]
    DIRECTION OUTPUT ;
    USE SIGNAL ;
    PORT
      LAYER M4 ;
        RECT  25.836 11.232 25.92 11.256 ;
    END
  END b[233]
  PIN b[234]
    DIRECTION OUTPUT ;
    USE SIGNAL ;
    PORT
      LAYER M4 ;
        RECT  25.836 11.376 25.92 11.4 ;
    END
  END b[234]
  PIN b[235]
    DIRECTION OUTPUT ;
    USE SIGNAL ;
    PORT
      LAYER M4 ;
        RECT  25.836 11.52 25.92 11.544 ;
    END
  END b[235]
  PIN b[236]
    DIRECTION OUTPUT ;
    USE SIGNAL ;
    PORT
      LAYER M4 ;
        RECT  25.836 11.664 25.92 11.688 ;
    END
  END b[236]
  PIN b[237]
    DIRECTION OUTPUT ;
    USE SIGNAL ;
    PORT
      LAYER M4 ;
        RECT  25.836 11.808 25.92 11.832 ;
    END
  END b[237]
  PIN b[238]
    DIRECTION OUTPUT ;
    USE SIGNAL ;
    PORT
      LAYER M4 ;
        RECT  25.836 11.952 25.92 11.976 ;
    END
  END b[238]
  PIN b[239]
    DIRECTION OUTPUT ;
    USE SIGNAL ;
    PORT
      LAYER M4 ;
        RECT  25.836 12.096 25.92 12.12 ;
    END
  END b[239]
  PIN b[23]
    DIRECTION OUTPUT ;
    USE SIGNAL ;
    PORT
      LAYER M4 ;
        RECT  25.836 46.656 25.92 46.68 ;
    END
  END b[23]
  PIN b[240]
    DIRECTION OUTPUT ;
    USE SIGNAL ;
    PORT
      LAYER M4 ;
        RECT  25.836 12.24 25.92 12.264 ;
    END
  END b[240]
  PIN b[241]
    DIRECTION OUTPUT ;
    USE SIGNAL ;
    PORT
      LAYER M4 ;
        RECT  25.836 12.384 25.92 12.408 ;
    END
  END b[241]
  PIN b[242]
    DIRECTION OUTPUT ;
    USE SIGNAL ;
    PORT
      LAYER M4 ;
        RECT  25.836 12.528 25.92 12.552 ;
    END
  END b[242]
  PIN b[243]
    DIRECTION OUTPUT ;
    USE SIGNAL ;
    PORT
      LAYER M4 ;
        RECT  25.836 12.672 25.92 12.696 ;
    END
  END b[243]
  PIN b[244]
    DIRECTION OUTPUT ;
    USE SIGNAL ;
    PORT
      LAYER M4 ;
        RECT  25.836 12.816 25.92 12.84 ;
    END
  END b[244]
  PIN b[245]
    DIRECTION OUTPUT ;
    USE SIGNAL ;
    PORT
      LAYER M4 ;
        RECT  25.836 12.96 25.92 12.984 ;
    END
  END b[245]
  PIN b[246]
    DIRECTION OUTPUT ;
    USE SIGNAL ;
    PORT
      LAYER M4 ;
        RECT  25.836 13.104 25.92 13.128 ;
    END
  END b[246]
  PIN b[247]
    DIRECTION OUTPUT ;
    USE SIGNAL ;
    PORT
      LAYER M4 ;
        RECT  25.836 13.248 25.92 13.272 ;
    END
  END b[247]
  PIN b[248]
    DIRECTION OUTPUT ;
    USE SIGNAL ;
    PORT
      LAYER M4 ;
        RECT  25.836 13.392 25.92 13.416 ;
    END
  END b[248]
  PIN b[249]
    DIRECTION OUTPUT ;
    USE SIGNAL ;
    PORT
      LAYER M4 ;
        RECT  25.836 13.536 25.92 13.56 ;
    END
  END b[249]
  PIN b[24]
    DIRECTION OUTPUT ;
    USE SIGNAL ;
    PORT
      LAYER M4 ;
        RECT  25.836 46.8 25.92 46.824 ;
    END
  END b[24]
  PIN b[250]
    DIRECTION OUTPUT ;
    USE SIGNAL ;
    PORT
      LAYER M4 ;
        RECT  25.836 13.68 25.92 13.704 ;
    END
  END b[250]
  PIN b[251]
    DIRECTION OUTPUT ;
    USE SIGNAL ;
    PORT
      LAYER M4 ;
        RECT  25.836 13.824 25.92 13.848 ;
    END
  END b[251]
  PIN b[252]
    DIRECTION OUTPUT ;
    USE SIGNAL ;
    PORT
      LAYER M4 ;
        RECT  25.836 13.968 25.92 13.992 ;
    END
  END b[252]
  PIN b[253]
    DIRECTION OUTPUT ;
    USE SIGNAL ;
    PORT
      LAYER M4 ;
        RECT  25.836 14.112 25.92 14.136 ;
    END
  END b[253]
  PIN b[254]
    DIRECTION OUTPUT ;
    USE SIGNAL ;
    PORT
      LAYER M4 ;
        RECT  25.836 14.256 25.92 14.28 ;
    END
  END b[254]
  PIN b[255]
    DIRECTION OUTPUT ;
    USE SIGNAL ;
    PORT
      LAYER M4 ;
        RECT  25.836 14.4 25.92 14.424 ;
    END
  END b[255]
  PIN b[256]
    DIRECTION OUTPUT ;
    USE SIGNAL ;
    PORT
      LAYER M4 ;
        RECT  25.836 23.76 25.92 23.784 ;
    END
  END b[256]
  PIN b[257]
    DIRECTION OUTPUT ;
    USE SIGNAL ;
    PORT
      LAYER M4 ;
        RECT  25.836 23.904 25.92 23.928 ;
    END
  END b[257]
  PIN b[258]
    DIRECTION OUTPUT ;
    USE SIGNAL ;
    PORT
      LAYER M4 ;
        RECT  25.836 24.048 25.92 24.072 ;
    END
  END b[258]
  PIN b[259]
    DIRECTION OUTPUT ;
    USE SIGNAL ;
    PORT
      LAYER M4 ;
        RECT  25.836 24.192 25.92 24.216 ;
    END
  END b[259]
  PIN b[25]
    DIRECTION OUTPUT ;
    USE SIGNAL ;
    PORT
      LAYER M4 ;
        RECT  25.836 46.944 25.92 46.968 ;
    END
  END b[25]
  PIN b[260]
    DIRECTION OUTPUT ;
    USE SIGNAL ;
    PORT
      LAYER M4 ;
        RECT  25.836 24.336 25.92 24.36 ;
    END
  END b[260]
  PIN b[261]
    DIRECTION OUTPUT ;
    USE SIGNAL ;
    PORT
      LAYER M4 ;
        RECT  25.836 24.48 25.92 24.504 ;
    END
  END b[261]
  PIN b[262]
    DIRECTION OUTPUT ;
    USE SIGNAL ;
    PORT
      LAYER M4 ;
        RECT  25.836 24.624 25.92 24.648 ;
    END
  END b[262]
  PIN b[263]
    DIRECTION OUTPUT ;
    USE SIGNAL ;
    PORT
      LAYER M4 ;
        RECT  25.836 24.768 25.92 24.792 ;
    END
  END b[263]
  PIN b[264]
    DIRECTION OUTPUT ;
    USE SIGNAL ;
    PORT
      LAYER M4 ;
        RECT  25.836 24.912 25.92 24.936 ;
    END
  END b[264]
  PIN b[265]
    DIRECTION OUTPUT ;
    USE SIGNAL ;
    PORT
      LAYER M4 ;
        RECT  25.836 25.056 25.92 25.08 ;
    END
  END b[265]
  PIN b[266]
    DIRECTION OUTPUT ;
    USE SIGNAL ;
    PORT
      LAYER M4 ;
        RECT  25.836 25.2 25.92 25.224 ;
    END
  END b[266]
  PIN b[267]
    DIRECTION OUTPUT ;
    USE SIGNAL ;
    PORT
      LAYER M4 ;
        RECT  25.836 25.344 25.92 25.368 ;
    END
  END b[267]
  PIN b[268]
    DIRECTION OUTPUT ;
    USE SIGNAL ;
    PORT
      LAYER M4 ;
        RECT  25.836 25.488 25.92 25.512 ;
    END
  END b[268]
  PIN b[269]
    DIRECTION OUTPUT ;
    USE SIGNAL ;
    PORT
      LAYER M4 ;
        RECT  25.836 25.632 25.92 25.656 ;
    END
  END b[269]
  PIN b[26]
    DIRECTION OUTPUT ;
    USE SIGNAL ;
    PORT
      LAYER M4 ;
        RECT  25.836 47.088 25.92 47.112 ;
    END
  END b[26]
  PIN b[270]
    DIRECTION OUTPUT ;
    USE SIGNAL ;
    PORT
      LAYER M4 ;
        RECT  25.836 25.776 25.92 25.8 ;
    END
  END b[270]
  PIN b[271]
    DIRECTION OUTPUT ;
    USE SIGNAL ;
    PORT
      LAYER M4 ;
        RECT  25.836 25.92 25.92 25.944 ;
    END
  END b[271]
  PIN b[272]
    DIRECTION OUTPUT ;
    USE SIGNAL ;
    PORT
      LAYER M4 ;
        RECT  25.836 26.064 25.92 26.088 ;
    END
  END b[272]
  PIN b[273]
    DIRECTION OUTPUT ;
    USE SIGNAL ;
    PORT
      LAYER M4 ;
        RECT  25.836 26.208 25.92 26.232 ;
    END
  END b[273]
  PIN b[274]
    DIRECTION OUTPUT ;
    USE SIGNAL ;
    PORT
      LAYER M4 ;
        RECT  25.836 26.352 25.92 26.376 ;
    END
  END b[274]
  PIN b[275]
    DIRECTION OUTPUT ;
    USE SIGNAL ;
    PORT
      LAYER M4 ;
        RECT  25.836 26.496 25.92 26.52 ;
    END
  END b[275]
  PIN b[276]
    DIRECTION OUTPUT ;
    USE SIGNAL ;
    PORT
      LAYER M4 ;
        RECT  25.836 26.64 25.92 26.664 ;
    END
  END b[276]
  PIN b[277]
    DIRECTION OUTPUT ;
    USE SIGNAL ;
    PORT
      LAYER M4 ;
        RECT  25.836 26.784 25.92 26.808 ;
    END
  END b[277]
  PIN b[278]
    DIRECTION OUTPUT ;
    USE SIGNAL ;
    PORT
      LAYER M4 ;
        RECT  25.836 26.928 25.92 26.952 ;
    END
  END b[278]
  PIN b[279]
    DIRECTION OUTPUT ;
    USE SIGNAL ;
    PORT
      LAYER M4 ;
        RECT  25.836 27.072 25.92 27.096 ;
    END
  END b[279]
  PIN b[27]
    DIRECTION OUTPUT ;
    USE SIGNAL ;
    PORT
      LAYER M4 ;
        RECT  25.836 47.232 25.92 47.256 ;
    END
  END b[27]
  PIN b[280]
    DIRECTION OUTPUT ;
    USE SIGNAL ;
    PORT
      LAYER M4 ;
        RECT  25.836 27.216 25.92 27.24 ;
    END
  END b[280]
  PIN b[281]
    DIRECTION OUTPUT ;
    USE SIGNAL ;
    PORT
      LAYER M4 ;
        RECT  25.836 27.36 25.92 27.384 ;
    END
  END b[281]
  PIN b[282]
    DIRECTION OUTPUT ;
    USE SIGNAL ;
    PORT
      LAYER M4 ;
        RECT  25.836 27.504 25.92 27.528 ;
    END
  END b[282]
  PIN b[283]
    DIRECTION OUTPUT ;
    USE SIGNAL ;
    PORT
      LAYER M4 ;
        RECT  25.836 27.648 25.92 27.672 ;
    END
  END b[283]
  PIN b[284]
    DIRECTION OUTPUT ;
    USE SIGNAL ;
    PORT
      LAYER M4 ;
        RECT  25.836 27.792 25.92 27.816 ;
    END
  END b[284]
  PIN b[285]
    DIRECTION OUTPUT ;
    USE SIGNAL ;
    PORT
      LAYER M4 ;
        RECT  25.836 27.936 25.92 27.96 ;
    END
  END b[285]
  PIN b[286]
    DIRECTION OUTPUT ;
    USE SIGNAL ;
    PORT
      LAYER M4 ;
        RECT  25.836 28.08 25.92 28.104 ;
    END
  END b[286]
  PIN b[287]
    DIRECTION OUTPUT ;
    USE SIGNAL ;
    PORT
      LAYER M4 ;
        RECT  25.836 28.224 25.92 28.248 ;
    END
  END b[287]
  PIN b[288]
    DIRECTION OUTPUT ;
    USE SIGNAL ;
    PORT
      LAYER M4 ;
        RECT  25.836 47.952 25.92 47.976 ;
    END
  END b[288]
  PIN b[289]
    DIRECTION OUTPUT ;
    USE SIGNAL ;
    PORT
      LAYER M4 ;
        RECT  25.836 48.096 25.92 48.12 ;
    END
  END b[289]
  PIN b[28]
    DIRECTION OUTPUT ;
    USE SIGNAL ;
    PORT
      LAYER M4 ;
        RECT  25.836 47.376 25.92 47.4 ;
    END
  END b[28]
  PIN b[290]
    DIRECTION OUTPUT ;
    USE SIGNAL ;
    PORT
      LAYER M4 ;
        RECT  25.836 48.24 25.92 48.264 ;
    END
  END b[290]
  PIN b[291]
    DIRECTION OUTPUT ;
    USE SIGNAL ;
    PORT
      LAYER M4 ;
        RECT  25.836 48.384 25.92 48.408 ;
    END
  END b[291]
  PIN b[292]
    DIRECTION OUTPUT ;
    USE SIGNAL ;
    PORT
      LAYER M4 ;
        RECT  25.836 48.528 25.92 48.552 ;
    END
  END b[292]
  PIN b[293]
    DIRECTION OUTPUT ;
    USE SIGNAL ;
    PORT
      LAYER M4 ;
        RECT  25.836 48.672 25.92 48.696 ;
    END
  END b[293]
  PIN b[294]
    DIRECTION OUTPUT ;
    USE SIGNAL ;
    PORT
      LAYER M4 ;
        RECT  25.836 48.816 25.92 48.84 ;
    END
  END b[294]
  PIN b[295]
    DIRECTION OUTPUT ;
    USE SIGNAL ;
    PORT
      LAYER M4 ;
        RECT  25.836 48.96 25.92 48.984 ;
    END
  END b[295]
  PIN b[29]
    DIRECTION OUTPUT ;
    USE SIGNAL ;
    PORT
      LAYER M4 ;
        RECT  25.836 47.52 25.92 47.544 ;
    END
  END b[29]
  PIN b[2]
    DIRECTION OUTPUT ;
    USE SIGNAL ;
    PORT
      LAYER M4 ;
        RECT  25.836 43.632 25.92 43.656 ;
    END
  END b[2]
  PIN b[30]
    DIRECTION OUTPUT ;
    USE SIGNAL ;
    PORT
      LAYER M4 ;
        RECT  25.836 47.664 25.92 47.688 ;
    END
  END b[30]
  PIN b[31]
    DIRECTION OUTPUT ;
    USE SIGNAL ;
    PORT
      LAYER M4 ;
        RECT  25.836 47.808 25.92 47.832 ;
    END
  END b[31]
  PIN b[32]
    DIRECTION OUTPUT ;
    USE SIGNAL ;
    PORT
      LAYER M4 ;
        RECT  25.836 5.328 25.92 5.352 ;
    END
  END b[32]
  PIN b[33]
    DIRECTION OUTPUT ;
    USE SIGNAL ;
    PORT
      LAYER M4 ;
        RECT  25.836 5.472 25.92 5.496 ;
    END
  END b[33]
  PIN b[34]
    DIRECTION OUTPUT ;
    USE SIGNAL ;
    PORT
      LAYER M4 ;
        RECT  25.836 5.616 25.92 5.64 ;
    END
  END b[34]
  PIN b[35]
    DIRECTION OUTPUT ;
    USE SIGNAL ;
    PORT
      LAYER M4 ;
        RECT  25.836 5.76 25.92 5.784 ;
    END
  END b[35]
  PIN b[36]
    DIRECTION OUTPUT ;
    USE SIGNAL ;
    PORT
      LAYER M4 ;
        RECT  25.836 5.904 25.92 5.928 ;
    END
  END b[36]
  PIN b[37]
    DIRECTION OUTPUT ;
    USE SIGNAL ;
    PORT
      LAYER M4 ;
        RECT  25.836 6.048 25.92 6.072 ;
    END
  END b[37]
  PIN b[38]
    DIRECTION OUTPUT ;
    USE SIGNAL ;
    PORT
      LAYER M4 ;
        RECT  25.836 6.192 25.92 6.216 ;
    END
  END b[38]
  PIN b[39]
    DIRECTION OUTPUT ;
    USE SIGNAL ;
    PORT
      LAYER M4 ;
        RECT  25.836 6.336 25.92 6.36 ;
    END
  END b[39]
  PIN b[3]
    DIRECTION OUTPUT ;
    USE SIGNAL ;
    PORT
      LAYER M4 ;
        RECT  25.836 43.776 25.92 43.8 ;
    END
  END b[3]
  PIN b[40]
    DIRECTION OUTPUT ;
    USE SIGNAL ;
    PORT
      LAYER M4 ;
        RECT  25.836 6.48 25.92 6.504 ;
    END
  END b[40]
  PIN b[41]
    DIRECTION OUTPUT ;
    USE SIGNAL ;
    PORT
      LAYER M4 ;
        RECT  25.836 6.624 25.92 6.648 ;
    END
  END b[41]
  PIN b[42]
    DIRECTION OUTPUT ;
    USE SIGNAL ;
    PORT
      LAYER M4 ;
        RECT  25.836 6.768 25.92 6.792 ;
    END
  END b[42]
  PIN b[43]
    DIRECTION OUTPUT ;
    USE SIGNAL ;
    PORT
      LAYER M4 ;
        RECT  25.836 6.912 25.92 6.936 ;
    END
  END b[43]
  PIN b[44]
    DIRECTION OUTPUT ;
    USE SIGNAL ;
    PORT
      LAYER M4 ;
        RECT  25.836 7.056 25.92 7.08 ;
    END
  END b[44]
  PIN b[45]
    DIRECTION OUTPUT ;
    USE SIGNAL ;
    PORT
      LAYER M4 ;
        RECT  25.836 7.2 25.92 7.224 ;
    END
  END b[45]
  PIN b[46]
    DIRECTION OUTPUT ;
    USE SIGNAL ;
    PORT
      LAYER M4 ;
        RECT  25.836 7.344 25.92 7.368 ;
    END
  END b[46]
  PIN b[47]
    DIRECTION OUTPUT ;
    USE SIGNAL ;
    PORT
      LAYER M4 ;
        RECT  25.836 7.488 25.92 7.512 ;
    END
  END b[47]
  PIN b[48]
    DIRECTION OUTPUT ;
    USE SIGNAL ;
    PORT
      LAYER M4 ;
        RECT  25.836 7.632 25.92 7.656 ;
    END
  END b[48]
  PIN b[49]
    DIRECTION OUTPUT ;
    USE SIGNAL ;
    PORT
      LAYER M4 ;
        RECT  25.836 7.776 25.92 7.8 ;
    END
  END b[49]
  PIN b[4]
    DIRECTION OUTPUT ;
    USE SIGNAL ;
    PORT
      LAYER M4 ;
        RECT  25.836 43.92 25.92 43.944 ;
    END
  END b[4]
  PIN b[50]
    DIRECTION OUTPUT ;
    USE SIGNAL ;
    PORT
      LAYER M4 ;
        RECT  25.836 7.92 25.92 7.944 ;
    END
  END b[50]
  PIN b[51]
    DIRECTION OUTPUT ;
    USE SIGNAL ;
    PORT
      LAYER M4 ;
        RECT  25.836 8.064 25.92 8.088 ;
    END
  END b[51]
  PIN b[52]
    DIRECTION OUTPUT ;
    USE SIGNAL ;
    PORT
      LAYER M4 ;
        RECT  25.836 8.208 25.92 8.232 ;
    END
  END b[52]
  PIN b[53]
    DIRECTION OUTPUT ;
    USE SIGNAL ;
    PORT
      LAYER M4 ;
        RECT  25.836 8.352 25.92 8.376 ;
    END
  END b[53]
  PIN b[54]
    DIRECTION OUTPUT ;
    USE SIGNAL ;
    PORT
      LAYER M4 ;
        RECT  25.836 8.496 25.92 8.52 ;
    END
  END b[54]
  PIN b[55]
    DIRECTION OUTPUT ;
    USE SIGNAL ;
    PORT
      LAYER M4 ;
        RECT  25.836 8.64 25.92 8.664 ;
    END
  END b[55]
  PIN b[56]
    DIRECTION OUTPUT ;
    USE SIGNAL ;
    PORT
      LAYER M4 ;
        RECT  25.836 8.784 25.92 8.808 ;
    END
  END b[56]
  PIN b[57]
    DIRECTION OUTPUT ;
    USE SIGNAL ;
    PORT
      LAYER M4 ;
        RECT  25.836 8.928 25.92 8.952 ;
    END
  END b[57]
  PIN b[58]
    DIRECTION OUTPUT ;
    USE SIGNAL ;
    PORT
      LAYER M4 ;
        RECT  25.836 9.072 25.92 9.096 ;
    END
  END b[58]
  PIN b[59]
    DIRECTION OUTPUT ;
    USE SIGNAL ;
    PORT
      LAYER M4 ;
        RECT  25.836 9.216 25.92 9.24 ;
    END
  END b[59]
  PIN b[5]
    DIRECTION OUTPUT ;
    USE SIGNAL ;
    PORT
      LAYER M4 ;
        RECT  25.836 44.064 25.92 44.088 ;
    END
  END b[5]
  PIN b[60]
    DIRECTION OUTPUT ;
    USE SIGNAL ;
    PORT
      LAYER M4 ;
        RECT  25.836 9.36 25.92 9.384 ;
    END
  END b[60]
  PIN b[61]
    DIRECTION OUTPUT ;
    USE SIGNAL ;
    PORT
      LAYER M4 ;
        RECT  25.836 9.504 25.92 9.528 ;
    END
  END b[61]
  PIN b[62]
    DIRECTION OUTPUT ;
    USE SIGNAL ;
    PORT
      LAYER M4 ;
        RECT  25.836 9.648 25.92 9.672 ;
    END
  END b[62]
  PIN b[63]
    DIRECTION OUTPUT ;
    USE SIGNAL ;
    PORT
      LAYER M4 ;
        RECT  25.836 9.792 25.92 9.816 ;
    END
  END b[63]
  PIN b[64]
    DIRECTION OUTPUT ;
    USE SIGNAL ;
    PORT
      LAYER M4 ;
        RECT  25.836 14.544 25.92 14.568 ;
    END
  END b[64]
  PIN b[65]
    DIRECTION OUTPUT ;
    USE SIGNAL ;
    PORT
      LAYER M4 ;
        RECT  25.836 14.688 25.92 14.712 ;
    END
  END b[65]
  PIN b[66]
    DIRECTION OUTPUT ;
    USE SIGNAL ;
    PORT
      LAYER M4 ;
        RECT  25.836 14.832 25.92 14.856 ;
    END
  END b[66]
  PIN b[67]
    DIRECTION OUTPUT ;
    USE SIGNAL ;
    PORT
      LAYER M4 ;
        RECT  25.836 14.976 25.92 15 ;
    END
  END b[67]
  PIN b[68]
    DIRECTION OUTPUT ;
    USE SIGNAL ;
    PORT
      LAYER M4 ;
        RECT  25.836 15.12 25.92 15.144 ;
    END
  END b[68]
  PIN b[69]
    DIRECTION OUTPUT ;
    USE SIGNAL ;
    PORT
      LAYER M4 ;
        RECT  25.836 15.264 25.92 15.288 ;
    END
  END b[69]
  PIN b[6]
    DIRECTION OUTPUT ;
    USE SIGNAL ;
    PORT
      LAYER M4 ;
        RECT  25.836 44.208 25.92 44.232 ;
    END
  END b[6]
  PIN b[70]
    DIRECTION OUTPUT ;
    USE SIGNAL ;
    PORT
      LAYER M4 ;
        RECT  25.836 15.408 25.92 15.432 ;
    END
  END b[70]
  PIN b[71]
    DIRECTION OUTPUT ;
    USE SIGNAL ;
    PORT
      LAYER M4 ;
        RECT  25.836 15.552 25.92 15.576 ;
    END
  END b[71]
  PIN b[72]
    DIRECTION OUTPUT ;
    USE SIGNAL ;
    PORT
      LAYER M4 ;
        RECT  25.836 15.696 25.92 15.72 ;
    END
  END b[72]
  PIN b[73]
    DIRECTION OUTPUT ;
    USE SIGNAL ;
    PORT
      LAYER M4 ;
        RECT  25.836 15.84 25.92 15.864 ;
    END
  END b[73]
  PIN b[74]
    DIRECTION OUTPUT ;
    USE SIGNAL ;
    PORT
      LAYER M4 ;
        RECT  25.836 15.984 25.92 16.008 ;
    END
  END b[74]
  PIN b[75]
    DIRECTION OUTPUT ;
    USE SIGNAL ;
    PORT
      LAYER M4 ;
        RECT  25.836 16.128 25.92 16.152 ;
    END
  END b[75]
  PIN b[76]
    DIRECTION OUTPUT ;
    USE SIGNAL ;
    PORT
      LAYER M4 ;
        RECT  25.836 16.272 25.92 16.296 ;
    END
  END b[76]
  PIN b[77]
    DIRECTION OUTPUT ;
    USE SIGNAL ;
    PORT
      LAYER M4 ;
        RECT  25.836 16.416 25.92 16.44 ;
    END
  END b[77]
  PIN b[78]
    DIRECTION OUTPUT ;
    USE SIGNAL ;
    PORT
      LAYER M4 ;
        RECT  25.836 16.56 25.92 16.584 ;
    END
  END b[78]
  PIN b[79]
    DIRECTION OUTPUT ;
    USE SIGNAL ;
    PORT
      LAYER M4 ;
        RECT  25.836 16.704 25.92 16.728 ;
    END
  END b[79]
  PIN b[7]
    DIRECTION OUTPUT ;
    USE SIGNAL ;
    PORT
      LAYER M4 ;
        RECT  25.836 44.352 25.92 44.376 ;
    END
  END b[7]
  PIN b[80]
    DIRECTION OUTPUT ;
    USE SIGNAL ;
    PORT
      LAYER M4 ;
        RECT  25.836 16.848 25.92 16.872 ;
    END
  END b[80]
  PIN b[81]
    DIRECTION OUTPUT ;
    USE SIGNAL ;
    PORT
      LAYER M4 ;
        RECT  25.836 16.992 25.92 17.016 ;
    END
  END b[81]
  PIN b[82]
    DIRECTION OUTPUT ;
    USE SIGNAL ;
    PORT
      LAYER M4 ;
        RECT  25.836 17.136 25.92 17.16 ;
    END
  END b[82]
  PIN b[83]
    DIRECTION OUTPUT ;
    USE SIGNAL ;
    PORT
      LAYER M4 ;
        RECT  25.836 17.28 25.92 17.304 ;
    END
  END b[83]
  PIN b[84]
    DIRECTION OUTPUT ;
    USE SIGNAL ;
    PORT
      LAYER M4 ;
        RECT  25.836 17.424 25.92 17.448 ;
    END
  END b[84]
  PIN b[85]
    DIRECTION OUTPUT ;
    USE SIGNAL ;
    PORT
      LAYER M4 ;
        RECT  25.836 17.568 25.92 17.592 ;
    END
  END b[85]
  PIN b[86]
    DIRECTION OUTPUT ;
    USE SIGNAL ;
    PORT
      LAYER M4 ;
        RECT  25.836 17.712 25.92 17.736 ;
    END
  END b[86]
  PIN b[87]
    DIRECTION OUTPUT ;
    USE SIGNAL ;
    PORT
      LAYER M4 ;
        RECT  25.836 17.856 25.92 17.88 ;
    END
  END b[87]
  PIN b[88]
    DIRECTION OUTPUT ;
    USE SIGNAL ;
    PORT
      LAYER M4 ;
        RECT  25.836 18 25.92 18.024 ;
    END
  END b[88]
  PIN b[89]
    DIRECTION OUTPUT ;
    USE SIGNAL ;
    PORT
      LAYER M4 ;
        RECT  25.836 18.144 25.92 18.168 ;
    END
  END b[89]
  PIN b[8]
    DIRECTION OUTPUT ;
    USE SIGNAL ;
    PORT
      LAYER M4 ;
        RECT  25.836 44.496 25.92 44.52 ;
    END
  END b[8]
  PIN b[90]
    DIRECTION OUTPUT ;
    USE SIGNAL ;
    PORT
      LAYER M4 ;
        RECT  25.836 18.288 25.92 18.312 ;
    END
  END b[90]
  PIN b[91]
    DIRECTION OUTPUT ;
    USE SIGNAL ;
    PORT
      LAYER M4 ;
        RECT  25.836 18.432 25.92 18.456 ;
    END
  END b[91]
  PIN b[92]
    DIRECTION OUTPUT ;
    USE SIGNAL ;
    PORT
      LAYER M4 ;
        RECT  25.836 18.576 25.92 18.6 ;
    END
  END b[92]
  PIN b[93]
    DIRECTION OUTPUT ;
    USE SIGNAL ;
    PORT
      LAYER M4 ;
        RECT  25.836 18.72 25.92 18.744 ;
    END
  END b[93]
  PIN b[94]
    DIRECTION OUTPUT ;
    USE SIGNAL ;
    PORT
      LAYER M4 ;
        RECT  25.836 18.864 25.92 18.888 ;
    END
  END b[94]
  PIN b[95]
    DIRECTION OUTPUT ;
    USE SIGNAL ;
    PORT
      LAYER M4 ;
        RECT  25.836 19.008 25.92 19.032 ;
    END
  END b[95]
  PIN b[96]
    DIRECTION OUTPUT ;
    USE SIGNAL ;
    PORT
      LAYER M4 ;
        RECT  25.836 38.736 25.92 38.76 ;
    END
  END b[96]
  PIN b[97]
    DIRECTION OUTPUT ;
    USE SIGNAL ;
    PORT
      LAYER M4 ;
        RECT  25.836 38.88 25.92 38.904 ;
    END
  END b[97]
  PIN b[98]
    DIRECTION OUTPUT ;
    USE SIGNAL ;
    PORT
      LAYER M4 ;
        RECT  25.836 39.024 25.92 39.048 ;
    END
  END b[98]
  PIN b[99]
    DIRECTION OUTPUT ;
    USE SIGNAL ;
    PORT
      LAYER M4 ;
        RECT  25.836 39.168 25.92 39.192 ;
    END
  END b[99]
  PIN b[9]
    DIRECTION OUTPUT ;
    USE SIGNAL ;
    PORT
      LAYER M4 ;
        RECT  25.836 44.64 25.92 44.664 ;
    END
  END b[9]
  PIN ck
    DIRECTION INPUT ;
    USE SIGNAL ;
    PORT
      LAYER M5 ;
        RECT  10.8 0 10.824 0.084 ;
    END
  END ck
  PIN rst_n
    DIRECTION INPUT ;
    USE SIGNAL ;
    PORT
      LAYER M5 ;
        RECT  10.944 0 10.968 0.084 ;
    END
  END rst_n
  PIN VDD
    DIRECTION INOUT ;
    USE POWER ;
    PORT
      LAYER M5 ;
        RECT  21.492 2.151 21.612 49.689 ;
        RECT  18.792 2.151 18.912 49.689 ;
        RECT  16.092 2.151 16.212 49.689 ;
        RECT  13.392 2.151 13.512 49.689 ;
        RECT  10.692 2.151 10.812 49.689 ;
        RECT  7.992 2.151 8.112 49.689 ;
        RECT  5.292 2.151 5.412 49.689 ;
        RECT  2.592 2.151 2.712 49.689 ;
    END
  END VDD
  PIN VSS
    DIRECTION INOUT ;
    USE GROUND ;
    PORT
      LAYER M5 ;
        RECT  21.3 2.137 21.42 49.703 ;
        RECT  18.6 2.137 18.72 49.703 ;
        RECT  15.9 2.137 16.02 49.703 ;
        RECT  13.2 2.137 13.32 49.703 ;
        RECT  10.5 2.137 10.62 49.703 ;
        RECT  7.8 2.137 7.92 49.703 ;
        RECT  5.1 2.137 5.22 49.703 ;
        RECT  2.4 2.137 2.52 49.703 ;
    END
  END VSS
  OBS
    LAYER RVTN ;
     RECT  2.16 2.16 23.76 2.295 ;
     RECT  2.16 2.565 23.76 2.835 ;
     RECT  2.16 3.105 23.76 3.375 ;
     RECT  2.16 3.645 23.76 3.915 ;
     RECT  2.16 4.185 23.76 4.455 ;
     RECT  2.16 4.725 23.76 4.995 ;
     RECT  2.16 5.265 23.76 5.535 ;
     RECT  2.16 5.805 23.76 6.075 ;
     RECT  2.16 6.345 23.76 6.615 ;
     RECT  2.16 6.885 23.76 7.155 ;
     RECT  2.16 7.425 23.76 7.695 ;
     RECT  2.16 7.965 23.76 8.235 ;
     RECT  2.16 8.505 23.76 8.775 ;
     RECT  2.16 9.045 23.76 9.315 ;
     RECT  2.16 9.585 23.76 9.855 ;
     RECT  2.16 10.125 23.76 10.395 ;
     RECT  2.16 10.665 23.76 10.935 ;
     RECT  2.16 11.205 23.76 11.475 ;
     RECT  2.16 11.745 23.76 12.015 ;
     RECT  2.16 12.285 23.76 12.555 ;
     RECT  2.16 12.825 23.76 13.095 ;
     RECT  2.16 13.365 23.76 13.635 ;
     RECT  2.16 13.905 23.76 14.175 ;
     RECT  2.16 14.445 23.76 14.715 ;
     RECT  2.16 14.985 23.76 15.255 ;
     RECT  2.16 15.525 23.76 15.795 ;
     RECT  2.16 16.065 23.76 16.335 ;
     RECT  2.16 16.605 23.76 16.875 ;
     RECT  2.16 17.145 23.76 17.415 ;
     RECT  2.16 17.685 23.76 17.955 ;
     RECT  2.16 18.225 23.76 18.495 ;
     RECT  2.16 18.765 23.76 19.035 ;
     RECT  2.16 19.305 23.76 19.575 ;
     RECT  2.16 19.845 23.76 20.115 ;
     RECT  2.16 20.385 23.76 20.655 ;
     RECT  2.16 20.925 23.76 21.195 ;
     RECT  2.16 21.465 23.76 21.735 ;
     RECT  2.16 22.005 23.76 22.275 ;
     RECT  2.16 22.545 23.76 22.815 ;
     RECT  2.16 23.085 23.76 23.355 ;
     RECT  2.16 23.625 23.76 23.895 ;
     RECT  2.16 24.165 23.76 24.435 ;
     RECT  2.16 24.705 23.76 24.975 ;
     RECT  2.16 25.245 23.76 25.515 ;
     RECT  2.16 25.785 23.76 26.055 ;
     RECT  2.16 26.325 23.76 26.595 ;
     RECT  2.16 26.865 23.76 27.135 ;
     RECT  2.16 27.405 23.76 27.675 ;
     RECT  2.16 27.945 23.76 28.215 ;
     RECT  2.16 28.485 23.76 28.755 ;
     RECT  2.16 29.025 23.76 29.295 ;
     RECT  2.16 29.565 23.76 29.835 ;
     RECT  2.16 30.105 23.76 30.375 ;
     RECT  2.16 30.645 23.76 30.915 ;
     RECT  2.16 31.185 23.76 31.455 ;
     RECT  2.16 31.725 23.76 31.995 ;
     RECT  2.16 32.265 23.76 32.535 ;
     RECT  2.16 32.805 23.76 33.075 ;
     RECT  2.16 33.345 23.76 33.615 ;
     RECT  2.16 33.885 23.76 34.155 ;
     RECT  2.16 34.425 23.76 34.695 ;
     RECT  2.16 34.965 23.76 35.235 ;
     RECT  2.16 35.505 23.76 35.775 ;
     RECT  2.16 36.045 23.76 36.315 ;
     RECT  2.16 36.585 23.76 36.855 ;
     RECT  2.16 37.125 23.76 37.395 ;
     RECT  2.16 37.665 23.76 37.935 ;
     RECT  2.16 38.205 23.76 38.475 ;
     RECT  2.16 38.745 23.76 39.015 ;
     RECT  2.16 39.285 23.76 39.555 ;
     RECT  2.16 39.825 23.76 40.095 ;
     RECT  2.16 40.365 23.76 40.635 ;
     RECT  2.16 40.905 23.76 41.175 ;
     RECT  2.16 41.445 23.76 41.715 ;
     RECT  2.16 41.985 23.76 42.255 ;
     RECT  2.16 42.525 23.76 42.795 ;
     RECT  2.16 43.065 23.76 43.335 ;
     RECT  2.16 43.605 23.76 43.875 ;
     RECT  2.16 44.145 23.76 44.415 ;
     RECT  2.16 44.685 23.76 44.955 ;
     RECT  2.16 45.225 23.76 45.495 ;
     RECT  2.16 45.765 23.76 46.035 ;
     RECT  2.16 46.305 23.76 46.575 ;
     RECT  2.16 46.845 23.76 47.115 ;
     RECT  2.16 47.385 23.76 47.655 ;
     RECT  2.16 47.925 23.76 48.195 ;
     RECT  2.16 48.465 23.76 48.735 ;
     RECT  2.16 49.005 23.76 49.275 ;
     RECT  2.16 49.545 23.76 49.68 ;
    LAYER RVTP ;
     RECT  2.16 2.295 23.76 2.565 ;
     RECT  2.16 2.835 23.76 3.105 ;
     RECT  2.16 3.375 23.76 3.645 ;
     RECT  2.16 3.915 23.76 4.185 ;
     RECT  2.16 4.455 23.76 4.725 ;
     RECT  2.16 4.995 23.76 5.265 ;
     RECT  2.16 5.535 23.76 5.805 ;
     RECT  2.16 6.075 23.76 6.345 ;
     RECT  2.16 6.615 23.76 6.885 ;
     RECT  2.16 7.155 23.76 7.425 ;
     RECT  2.16 7.695 23.76 7.965 ;
     RECT  2.16 8.235 23.76 8.505 ;
     RECT  2.16 8.775 23.76 9.045 ;
     RECT  2.16 9.315 23.76 9.585 ;
     RECT  2.16 9.855 23.76 10.125 ;
     RECT  2.16 10.395 23.76 10.665 ;
     RECT  2.16 10.935 23.76 11.205 ;
     RECT  2.16 11.475 23.76 11.745 ;
     RECT  2.16 12.015 23.76 12.285 ;
     RECT  2.16 12.555 23.76 12.825 ;
     RECT  2.16 13.095 23.76 13.365 ;
     RECT  2.16 13.635 23.76 13.905 ;
     RECT  2.16 14.175 23.76 14.445 ;
     RECT  2.16 14.715 23.76 14.985 ;
     RECT  2.16 15.255 23.76 15.525 ;
     RECT  2.16 15.795 23.76 16.065 ;
     RECT  2.16 16.335 23.76 16.605 ;
     RECT  2.16 16.875 23.76 17.145 ;
     RECT  2.16 17.415 23.76 17.685 ;
     RECT  2.16 17.955 23.76 18.225 ;
     RECT  2.16 18.495 23.76 18.765 ;
     RECT  2.16 19.035 23.76 19.305 ;
     RECT  2.16 19.575 23.76 19.845 ;
     RECT  2.16 20.115 23.76 20.385 ;
     RECT  2.16 20.655 23.76 20.925 ;
     RECT  2.16 21.195 23.76 21.465 ;
     RECT  2.16 21.735 23.76 22.005 ;
     RECT  2.16 22.275 23.76 22.545 ;
     RECT  2.16 22.815 23.76 23.085 ;
     RECT  2.16 23.355 23.76 23.625 ;
     RECT  2.16 23.895 23.76 24.165 ;
     RECT  2.16 24.435 23.76 24.705 ;
     RECT  2.16 24.975 23.76 25.245 ;
     RECT  2.16 25.515 23.76 25.785 ;
     RECT  2.16 26.055 23.76 26.325 ;
     RECT  2.16 26.595 23.76 26.865 ;
     RECT  2.16 27.135 23.76 27.405 ;
     RECT  2.16 27.675 23.76 27.945 ;
     RECT  2.16 28.215 23.76 28.485 ;
     RECT  2.16 28.755 23.76 29.025 ;
     RECT  2.16 29.295 23.76 29.565 ;
     RECT  2.16 29.835 23.76 30.105 ;
     RECT  2.16 30.375 23.76 30.645 ;
     RECT  2.16 30.915 23.76 31.185 ;
     RECT  2.16 31.455 23.76 31.725 ;
     RECT  2.16 31.995 23.76 32.265 ;
     RECT  2.16 32.535 23.76 32.805 ;
     RECT  2.16 33.075 23.76 33.345 ;
     RECT  2.16 33.615 23.76 33.885 ;
     RECT  2.16 34.155 23.76 34.425 ;
     RECT  2.16 34.695 23.76 34.965 ;
     RECT  2.16 35.235 23.76 35.505 ;
     RECT  2.16 35.775 23.76 36.045 ;
     RECT  2.16 36.315 23.76 36.585 ;
     RECT  2.16 36.855 23.76 37.125 ;
     RECT  2.16 37.395 23.76 37.665 ;
     RECT  2.16 37.935 23.76 38.205 ;
     RECT  2.16 38.475 23.76 38.745 ;
     RECT  2.16 39.015 23.76 39.285 ;
     RECT  2.16 39.555 23.76 39.825 ;
     RECT  2.16 40.095 23.76 40.365 ;
     RECT  2.16 40.635 23.76 40.905 ;
     RECT  2.16 41.175 23.76 41.445 ;
     RECT  2.16 41.715 23.76 41.985 ;
     RECT  2.16 42.255 23.76 42.525 ;
     RECT  2.16 42.795 23.76 43.065 ;
     RECT  2.16 43.335 23.76 43.605 ;
     RECT  2.16 43.875 23.76 44.145 ;
     RECT  2.16 44.415 23.76 44.685 ;
     RECT  2.16 44.955 23.76 45.225 ;
     RECT  2.16 45.495 23.76 45.765 ;
     RECT  2.16 46.035 23.76 46.305 ;
     RECT  2.16 46.575 23.76 46.845 ;
     RECT  2.16 47.115 23.76 47.385 ;
     RECT  2.16 47.655 23.76 47.925 ;
     RECT  2.16 48.195 23.76 48.465 ;
     RECT  2.16 48.735 23.76 49.005 ;
     RECT  2.16 49.275 23.76 49.545 ;
    LAYER M1 ;
     RECT  2.16 2.151 23.76 49.689 ;
    LAYER M2 ;
     RECT  0.103 12.366 0.535 12.384 ;
     RECT  0.535 12.366 2.155 12.546 ;
     RECT  0.535 3.96 2.16 3.978 ;
     RECT  0.535 7.362 2.16 7.38 ;
     RECT  2.155 11.826 2.16 12.546 ;
     RECT  0.535 13.644 2.16 14.238 ;
     RECT  0.535 17.082 2.16 17.1 ;
     RECT  0.139 20.7 2.16 20.718 ;
     RECT  0.535 28.8 2.16 28.818 ;
     RECT  0.535 33.354 2.16 33.372 ;
     RECT  0.535 42.606 2.16 42.624 ;
     RECT  2.16 2.151 23.76 49.689 ;
     RECT  23.76 36.252 23.927 40.05 ;
     RECT  23.76 16.812 23.963 17.604 ;
     RECT  23.76 18.432 23.963 19.944 ;
     RECT  23.76 20.736 23.963 28.134 ;
     RECT  23.76 28.962 23.963 33.534 ;
     RECT  23.927 37.71 23.963 40.05 ;
     RECT  23.76 42.156 23.963 48.654 ;
     RECT  23.963 20.862 23.999 23.04 ;
     RECT  23.963 28.962 24.035 30.096 ;
     RECT  23.76 40.842 24.035 40.932 ;
     RECT  23.963 37.71 24.467 39.114 ;
     RECT  24.467 37.71 24.503 38.7 ;
     RECT  23.963 16.956 24.539 17.604 ;
     RECT  23.963 18.468 24.539 19.944 ;
     RECT  23.999 20.898 24.539 23.04 ;
     RECT  23.963 23.832 24.539 28.134 ;
     RECT  24.035 28.962 24.539 29.79 ;
     RECT  23.963 31.194 24.539 33.264 ;
     RECT  23.963 42.156 24.539 43.092 ;
     RECT  23.963 44.046 24.539 48.654 ;
     RECT  24.539 21.168 24.575 23.04 ;
     RECT  24.539 29.466 24.575 29.484 ;
     RECT  24.539 45.468 24.575 48.654 ;
     RECT  24.575 21.168 24.647 22.77 ;
     RECT  23.76 13.446 24.791 14.094 ;
     RECT  23.76 15.696 24.827 15.894 ;
     RECT  24.539 23.904 25.079 27.162 ;
     RECT  24.503 37.746 25.079 38.7 ;
     RECT  23.76 7.092 25.115 7.686 ;
     RECT  23.76 11.79 25.115 11.97 ;
     RECT  24.791 14.076 25.115 14.094 ;
     RECT  24.827 15.768 25.115 15.894 ;
     RECT  24.539 18.468 25.115 18.486 ;
     RECT  24.539 19.656 25.115 19.944 ;
     RECT  24.647 21.168 25.115 22.032 ;
     RECT  25.079 24.102 25.115 27.162 ;
     RECT  24.539 28.116 25.115 28.134 ;
     RECT  24.539 31.194 25.115 32.994 ;
     RECT  23.963 40.032 25.115 40.05 ;
     RECT  24.035 40.842 25.115 40.86 ;
     RECT  24.539 42.156 25.115 42.444 ;
     RECT  24.539 44.046 25.115 44.442 ;
     RECT  24.575 45.468 25.115 47.646 ;
     RECT  24.575 48.636 25.115 48.654 ;
     RECT  25.115 11.79 25.151 11.808 ;
     RECT  25.115 15.768 25.151 15.822 ;
     RECT  24.539 16.956 25.151 17.442 ;
     RECT  25.115 19.926 25.151 19.944 ;
     RECT  25.115 24.336 25.151 25.704 ;
     RECT  25.115 26.496 25.151 26.514 ;
     RECT  25.115 31.734 25.151 32.994 ;
     RECT  25.115 42.264 25.151 42.444 ;
     RECT  25.115 45.468 25.151 45.486 ;
     RECT  25.115 46.278 25.151 46.296 ;
     RECT  25.115 47.052 25.151 47.106 ;
     RECT  25.151 16.956 25.187 16.974 ;
     RECT  25.151 25.488 25.187 25.506 ;
     RECT  25.151 32.706 25.187 32.994 ;
     RECT  23.76 8.712 25.195 10.62 ;
     RECT  25.151 15.768 25.223 15.786 ;
     RECT  25.187 32.976 25.223 32.994 ;
     RECT  25.115 7.128 25.259 7.686 ;
     RECT  25.195 8.712 25.403 11.034 ;
     RECT  25.403 9.126 25.439 11.034 ;
     RECT  25.439 10.062 25.475 11.034 ;
     RECT  25.259 7.2 25.511 7.686 ;
     RECT  25.511 7.2 25.583 7.65 ;
     RECT  23.76 5.742 25.619 6.174 ;
     RECT  25.475 10.17 25.627 11.034 ;
     RECT  25.627 10.17 25.655 11.619 ;
     RECT  25.619 5.742 25.691 5.949 ;
     RECT  25.655 10.368 25.691 11.619 ;
     RECT  25.583 7.632 25.727 7.65 ;
     RECT  23.76 4.626 25.763 4.986 ;
     RECT  25.691 11.601 25.799 11.619 ;
     RECT  25.115 21.168 25.835 21.186 ;
     RECT  23.76 34.596 25.835 34.614 ;
     RECT  23.927 36.252 25.835 36.774 ;
     RECT  25.151 42.264 25.835 42.282 ;
     RECT  25.151 47.088 25.835 47.106 ;
     RECT  25.691 5.931 25.871 5.949 ;
     RECT  25.439 9.126 25.871 9.144 ;
     RECT  25.763 4.626 25.907 4.644 ;
     RECT  25.691 10.368 25.907 10.386 ;
    LAYER M3 ;
     RECT  10.944 1.723 10.962 2.143 ;
     RECT  10.515 2.143 10.962 2.371 ;
     RECT  2.415 2.143 2.505 2.413 ;
     RECT  5.115 2.143 5.205 2.413 ;
     RECT  7.815 2.143 7.905 2.413 ;
     RECT  13.215 2.143 13.305 2.413 ;
     RECT  15.915 2.143 16.005 2.413 ;
     RECT  18.615 2.143 18.705 2.413 ;
     RECT  21.315 2.143 21.405 2.413 ;
     RECT  10.515 2.371 11.07 3.299 ;
     RECT  10.515 3.299 10.854 3.437 ;
     RECT  5.115 2.413 5.397 3.847 ;
     RECT  2.415 2.413 2.697 3.883 ;
     RECT  4.176 3.883 4.194 3.955 ;
     RECT  3.96 3.955 4.194 3.991 ;
     RECT  5.115 3.847 5.598 3.991 ;
     RECT  0.54 3.955 0.558 4.061 ;
     RECT  2.415 3.883 2.898 4.072 ;
     RECT  3.96 3.991 5.778 4.072 ;
     RECT  2.415 4.072 5.778 4.117 ;
     RECT  6.552 4.081 6.57 4.117 ;
     RECT  10.515 3.437 10.797 4.261 ;
     RECT  2.415 4.117 6.858 4.315 ;
     RECT  7.815 2.413 8.097 4.459 ;
     RECT  7.815 4.459 8.622 4.495 ;
     RECT  2.304 4.315 6.858 4.531 ;
     RECT  7.815 4.495 8.946 4.531 ;
     RECT  14.4 4.117 14.418 4.531 ;
     RECT  9.936 4.261 10.797 4.657 ;
     RECT  14.4 4.531 14.85 4.729 ;
     RECT  9.936 4.657 10.89 4.757 ;
     RECT  2.304 4.531 8.946 4.765 ;
     RECT  2.304 4.765 9.162 4.801 ;
     RECT  9.936 4.757 10.818 4.801 ;
     RECT  15.915 2.413 16.197 4.801 ;
     RECT  2.304 4.801 10.818 4.835 ;
     RECT  7.236 4.835 10.818 4.919 ;
     RECT  25.884 4.621 25.902 4.927 ;
     RECT  7.236 4.919 9.162 5.189 ;
     RECT  14.256 4.729 14.85 5.189 ;
     RECT  21.315 2.413 21.597 5.323 ;
     RECT  13.215 2.413 13.497 5.341 ;
     RECT  15.768 4.801 16.197 5.341 ;
     RECT  0.144 5.227 0.162 5.357 ;
     RECT  21.204 5.323 21.597 5.369 ;
     RECT  11.772 3.451 11.79 5.467 ;
     RECT  12.564 5.341 13.497 5.467 ;
     RECT  9.936 4.919 10.818 5.503 ;
     RECT  14.724 5.189 14.85 5.539 ;
     RECT  15.768 5.341 16.722 5.539 ;
     RECT  7.236 5.189 9.018 5.603 ;
     RECT  9.936 5.503 10.926 5.611 ;
     RECT  21.315 5.369 21.597 5.611 ;
     RECT  2.304 4.835 6.426 5.701 ;
     RECT  9.936 5.611 10.962 5.701 ;
     RECT  11.772 5.467 13.497 5.701 ;
     RECT  25.632 4.927 25.902 5.773 ;
     RECT  0.18 5.803 0.198 5.933 ;
     RECT  7.308 5.603 9.018 5.971 ;
     RECT  14.724 5.539 16.722 5.995 ;
     RECT  2.304 5.701 6.57 5.999 ;
     RECT  14.652 5.995 16.722 6.043 ;
     RECT  25.092 5.773 25.902 6.043 ;
     RECT  14.652 6.043 17.154 6.079 ;
     RECT  14.652 6.079 17.838 6.269 ;
     RECT  18.615 2.413 18.897 6.421 ;
     RECT  14.652 6.269 14.67 6.619 ;
     RECT  21.315 5.611 21.726 6.719 ;
     RECT  21.315 6.719 21.69 6.797 ;
     RECT  14.4 6.619 14.67 6.809 ;
     RECT  2.304 5.999 6.426 6.917 ;
     RECT  3.96 6.917 6.426 6.961 ;
     RECT  7.308 5.971 9.162 6.961 ;
     RECT  21.315 6.797 21.597 7.051 ;
     RECT  0.144 6.379 0.162 7.181 ;
     RECT  3.96 6.961 9.162 7.195 ;
     RECT  9.936 5.701 13.497 7.195 ;
     RECT  18.216 6.421 19.206 7.195 ;
     RECT  3.96 7.195 13.497 7.385 ;
     RECT  15.768 6.269 16.722 7.387 ;
     RECT  3.96 7.385 9.198 7.457 ;
     RECT  14.652 6.809 14.67 7.483 ;
     RECT  21.204 7.051 21.597 7.529 ;
     RECT  14.652 7.483 14.85 7.627 ;
     RECT  9.936 7.385 13.497 7.933 ;
     RECT  14.22 7.627 14.85 7.933 ;
     RECT  0.54 7.357 0.558 7.949 ;
     RECT  2.304 6.917 3.222 8.267 ;
     RECT  2.412 8.267 3.222 8.311 ;
     RECT  3.96 7.457 6.57 8.311 ;
     RECT  7.308 7.457 9.198 8.311 ;
     RECT  9.936 7.933 14.85 8.311 ;
     RECT  7.308 8.311 14.85 8.401 ;
     RECT  15.768 7.387 17.262 8.401 ;
     RECT  21.315 7.529 21.597 8.671 ;
     RECT  2.412 8.311 6.57 8.699 ;
     RECT  21.204 8.671 21.597 8.717 ;
     RECT  0.144 8.635 0.162 8.765 ;
     RECT  3.96 8.699 6.57 8.779 ;
     RECT  7.308 8.401 17.262 8.779 ;
     RECT  3.96 8.779 17.262 8.807 ;
     RECT  3.96 8.807 14.85 8.843 ;
     RECT  23.076 5.467 23.094 8.923 ;
     RECT  3.996 8.843 14.85 8.969 ;
     RECT  2.412 8.699 3.222 9.067 ;
     RECT  2.304 9.067 3.222 9.211 ;
     RECT  10.044 8.969 14.85 9.341 ;
     RECT  2.268 9.211 3.222 9.545 ;
     RECT  15.732 8.807 17.262 9.547 ;
     RECT  24.768 6.043 25.902 9.589 ;
     RECT  21.315 8.717 21.597 9.643 ;
     RECT  21.204 9.643 21.597 9.689 ;
     RECT  2.304 9.545 3.222 9.824 ;
     RECT  3.996 8.969 9.306 9.895 ;
     RECT  24.516 9.589 25.902 9.965 ;
     RECT  3.96 9.895 9.306 10.085 ;
     RECT  10.044 9.341 14.814 10.129 ;
     RECT  15.696 9.547 17.262 10.129 ;
     RECT  4.068 10.085 9.306 10.165 ;
     RECT  10.044 10.129 17.262 10.165 ;
     RECT  24.768 9.965 25.902 10.391 ;
     RECT  24.768 10.391 25.83 10.4 ;
     RECT  0.144 9.547 0.162 10.637 ;
     RECT  4.068 10.165 17.262 10.733 ;
     RECT  15.48 10.733 17.262 10.769 ;
     RECT  2.415 9.824 3.222 10.795 ;
     RECT  2.304 10.795 3.222 11.011 ;
     RECT  0.18 11.083 0.198 11.213 ;
     RECT  2.304 11.011 3.258 11.245 ;
     RECT  4.068 10.733 14.742 11.245 ;
     RECT  2.304 11.245 14.742 11.641 ;
     RECT  15.516 10.769 17.262 11.641 ;
     RECT  18.108 7.195 19.206 11.741 ;
     RECT  2.304 11.641 17.262 11.803 ;
     RECT  2.16 11.803 17.262 11.849 ;
     RECT  21.315 9.689 21.597 11.983 ;
     RECT  4.068 11.849 17.262 12.209 ;
     RECT  0.108 12.361 0.126 12.413 ;
     RECT  21.315 11.983 21.654 12.487 ;
     RECT  2.304 11.849 3.258 12.551 ;
     RECT  0.144 12.517 0.558 12.557 ;
     RECT  4.104 12.209 17.262 12.929 ;
     RECT  23.076 8.923 23.238 13.019 ;
     RECT  4.104 12.929 6.498 13.027 ;
     RECT  7.272 12.929 17.262 13.163 ;
     RECT  20.484 13.063 20.502 13.289 ;
     RECT  2.304 12.551 2.862 13.369 ;
     RECT  3.888 13.027 6.498 13.369 ;
     RECT  21.315 12.487 22.266 13.421 ;
     RECT  24.768 10.4 25.794 13.469 ;
     RECT  21.315 13.421 21.597 13.531 ;
     RECT  20.376 13.441 20.394 13.559 ;
     RECT  23.22 13.019 23.238 13.567 ;
     RECT  21.204 13.531 21.597 13.568 ;
     RECT  7.308 13.163 17.262 13.603 ;
     RECT  18.108 11.741 18.897 13.603 ;
     RECT  0.144 12.557 0.162 13.639 ;
     RECT  0.144 13.639 0.558 13.661 ;
     RECT  23.22 13.567 23.958 13.997 ;
     RECT  2.304 13.369 6.498 14.107 ;
     RECT  7.308 13.603 18.897 14.107 ;
     RECT  2.304 14.107 18.897 14.144 ;
     RECT  7.308 14.144 18.897 14.369 ;
     RECT  0.54 13.661 0.558 14.429 ;
     RECT  17.928 14.369 18.897 14.549 ;
     RECT  0.144 14.539 0.162 14.669 ;
     RECT  18.504 14.549 18.897 14.819 ;
     RECT  2.304 14.144 6.498 14.945 ;
     RECT  23.22 13.997 23.238 14.953 ;
     RECT  24.804 13.469 25.794 15.005 ;
     RECT  23.22 14.953 23.382 15.149 ;
     RECT  7.308 14.369 17.082 15.359 ;
     RECT  25.776 15.005 25.794 15.437 ;
     RECT  23.22 15.149 23.274 15.457 ;
     RECT  10.26 15.359 17.082 15.629 ;
     RECT  10.296 15.629 17.082 15.691 ;
     RECT  10.296 15.691 17.19 15.719 ;
     RECT  24.804 15.005 24.822 15.719 ;
     RECT  2.304 14.945 6.426 15.755 ;
     RECT  10.368 15.719 17.19 15.791 ;
     RECT  0.144 15.691 0.162 15.821 ;
     RECT  22.824 15.457 23.274 15.827 ;
     RECT  22.824 15.827 23.238 15.899 ;
     RECT  4.032 15.755 6.426 15.961 ;
     RECT  22.896 15.899 23.238 15.989 ;
     RECT  21.315 13.568 21.597 16.105 ;
     RECT  25.092 15.763 25.218 16.157 ;
     RECT  23.22 15.989 23.238 16.259 ;
     RECT  10.368 15.791 16.686 16.301 ;
     RECT  20.808 16.105 21.597 16.339 ;
     RECT  20.808 16.339 21.69 16.445 ;
     RECT  20.808 16.445 21.597 16.529 ;
     RECT  7.308 15.359 9.486 16.681 ;
     RECT  10.368 16.301 12.006 16.681 ;
     RECT  7.308 16.681 12.006 16.799 ;
     RECT  12.816 16.301 16.686 16.799 ;
     RECT  4.032 15.961 6.57 16.915 ;
     RECT  7.308 16.799 9.522 16.915 ;
     RECT  4.032 16.915 9.522 16.939 ;
     RECT  25.2 16.157 25.218 16.951 ;
     RECT  10.26 16.799 11.898 16.979 ;
     RECT  23.94 16.807 23.958 17.021 ;
     RECT  15.624 16.799 16.686 17.041 ;
     RECT  15.624 17.041 17.118 17.069 ;
     RECT  0.54 17.077 0.558 17.165 ;
     RECT  25.164 16.951 25.218 17.179 ;
     RECT  2.304 15.755 3.258 17.185 ;
     RECT  3.996 16.939 9.522 17.185 ;
     RECT  25.164 17.179 25.758 17.309 ;
     RECT  18.576 14.819 18.897 17.311 ;
     RECT  2.304 17.185 9.522 17.339 ;
     RECT  12.816 16.799 14.346 17.339 ;
     RECT  17.1 17.069 17.118 17.339 ;
     RECT  25.164 17.309 25.182 17.347 ;
     RECT  21.315 16.529 21.597 17.383 ;
     RECT  18.144 17.311 18.897 17.411 ;
     RECT  13.215 17.339 14.346 17.453 ;
     RECT  3.96 17.339 9.522 17.483 ;
     RECT  19.656 17.347 19.674 17.519 ;
     RECT  3.996 17.483 9.522 17.581 ;
     RECT  10.26 16.979 11.826 17.581 ;
     RECT  25.092 17.347 25.182 17.581 ;
     RECT  21.315 17.383 21.69 17.725 ;
     RECT  3.996 17.581 11.826 17.761 ;
     RECT  24.516 17.581 25.182 17.885 ;
     RECT  3.996 17.761 12.006 17.887 ;
     RECT  3.996 17.887 12.042 17.923 ;
     RECT  0.144 17.851 0.162 17.981 ;
     RECT  15.624 17.069 16.197 18.029 ;
     RECT  15.915 18.029 16.197 18.031 ;
     RECT  3.996 17.923 12.078 18.059 ;
     RECT  15.915 18.031 16.398 18.149 ;
     RECT  21.315 17.725 21.762 18.157 ;
     RECT  13.215 17.453 14.13 18.193 ;
     RECT  13.104 18.193 14.13 18.257 ;
     RECT  13.104 18.257 13.554 18.265 ;
     RECT  3.996 18.059 12.042 18.419 ;
     RECT  24.516 17.885 25.11 18.427 ;
     RECT  14.868 18.427 14.886 18.463 ;
     RECT  14.436 18.463 14.958 18.563 ;
     RECT  21.096 18.157 21.762 18.661 ;
     RECT  17.244 18.571 17.262 18.689 ;
     RECT  3.996 18.419 11.97 18.725 ;
     RECT  21.096 18.661 22.266 18.749 ;
     RECT  18.615 17.411 18.897 18.769 ;
     RECT  12.78 18.265 13.554 18.797 ;
     RECT  23.94 18.427 25.11 18.893 ;
     RECT  21.315 18.749 22.266 18.959 ;
     RECT  2.304 17.339 3.222 19.111 ;
     RECT  3.996 18.725 5.634 19.229 ;
     RECT  6.408 18.725 11.97 19.273 ;
     RECT  12.78 18.797 13.497 19.273 ;
     RECT  6.408 19.273 13.497 19.301 ;
     RECT  14.436 18.563 14.85 19.507 ;
     RECT  11.736 19.301 13.497 19.613 ;
     RECT  12.492 19.613 13.497 19.651 ;
     RECT  14.436 19.507 14.922 19.651 ;
     RECT  23.94 18.893 24.534 19.651 ;
     RECT  12.492 19.651 14.922 19.679 ;
     RECT  22.86 19.507 22.878 19.757 ;
     RECT  18.615 18.769 18.954 19.769 ;
     RECT  20.304 19.651 20.322 19.769 ;
     RECT  23.94 19.651 25.11 19.813 ;
     RECT  0.144 19.723 0.162 19.853 ;
     RECT  20.376 19.777 20.394 19.877 ;
     RECT  23.364 19.813 25.11 19.921 ;
     RECT  6.408 19.301 10.89 20.011 ;
     RECT  23.364 19.921 25.146 20.045 ;
     RECT  11.736 19.613 11.754 20.155 ;
     RECT  11.7 20.155 11.754 20.189 ;
     RECT  3.996 19.229 5.454 20.425 ;
     RECT  6.336 20.011 10.89 20.425 ;
     RECT  21.315 18.959 21.597 20.551 ;
     RECT  23.364 20.045 24.534 20.621 ;
     RECT  21.096 20.551 21.597 20.623 ;
     RECT  12.492 19.679 14.274 20.695 ;
     RECT  18.615 19.769 18.897 20.731 ;
     RECT  21.096 20.623 21.69 20.765 ;
     RECT  12.492 20.695 14.958 20.849 ;
     RECT  17.1 20.191 17.118 20.849 ;
     RECT  18.324 20.731 18.897 20.849 ;
     RECT  2.304 19.111 3.258 20.885 ;
     RECT  3.996 20.425 10.89 20.885 ;
     RECT  21.096 20.765 21.597 20.909 ;
     RECT  11.7 20.189 11.718 20.965 ;
     RECT  15.915 18.149 16.197 21.001 ;
     RECT  23.94 20.621 24.534 21.053 ;
     RECT  6.876 20.885 10.89 21.091 ;
     RECT  11.7 20.965 11.754 21.091 ;
     RECT  2.412 20.885 3.258 21.115 ;
     RECT  3.996 20.885 6.138 21.115 ;
     RECT  23.976 21.053 24.534 21.197 ;
     RECT  25.812 21.163 25.83 21.341 ;
     RECT  24.516 21.197 24.534 21.361 ;
     RECT  6.876 21.091 11.754 21.389 ;
     RECT  12.492 20.849 14.094 21.541 ;
     RECT  15.696 21.001 16.197 21.541 ;
     RECT  0.144 20.695 0.162 21.629 ;
     RECT  2.412 21.115 6.138 21.659 ;
     RECT  4.032 21.659 6.138 21.775 ;
     RECT  6.876 21.389 11.034 21.775 ;
     RECT  21.315 20.909 21.597 21.775 ;
     RECT  15.624 21.541 16.197 21.811 ;
     RECT  14.868 20.849 14.886 21.901 ;
     RECT  15.624 21.811 16.434 21.901 ;
     RECT  24.516 21.361 25.758 21.917 ;
     RECT  11.952 21.541 14.094 21.929 ;
     RECT  14.868 21.901 16.434 21.929 ;
     RECT  24.516 21.917 25.11 21.973 ;
     RECT  21.315 21.775 22.266 22.061 ;
     RECT  14.868 21.929 16.254 22.109 ;
     RECT  2.412 21.659 3.258 22.171 ;
     RECT  15.84 22.109 16.254 22.199 ;
     RECT  4.032 21.775 11.034 22.207 ;
     RECT  11.952 21.929 13.497 22.207 ;
     RECT  23.94 21.973 25.11 22.349 ;
     RECT  15.915 22.199 16.254 22.379 ;
     RECT  4.032 22.207 13.497 22.493 ;
     RECT  24.516 22.349 25.11 22.637 ;
     RECT  12.6 22.493 13.497 22.739 ;
     RECT  12.672 22.739 13.497 22.747 ;
     RECT  14.832 22.621 14.85 22.775 ;
     RECT  18.615 20.849 18.897 22.855 ;
     RECT  12.672 22.747 14.022 23.009 ;
     RECT  17.784 22.171 17.802 23.009 ;
     RECT  2.304 22.171 3.258 23.017 ;
     RECT  4.032 22.493 11.682 23.017 ;
     RECT  2.304 23.017 11.682 23.117 ;
     RECT  14.472 23.017 14.49 23.189 ;
     RECT  12.672 23.009 13.698 23.279 ;
     RECT  23.364 22.981 23.382 23.357 ;
     RECT  15.915 22.379 16.197 23.395 ;
     RECT  22.32 23.251 22.338 23.431 ;
     RECT  24.516 22.637 24.642 23.521 ;
     RECT  3.96 23.117 11.682 23.645 ;
     RECT  23.94 23.521 24.642 23.789 ;
     RECT  12.816 23.279 13.698 23.791 ;
     RECT  24.516 23.789 24.642 23.899 ;
     RECT  12.816 23.791 14.382 23.927 ;
     RECT  0.324 23.755 0.342 23.933 ;
     RECT  18.615 22.855 18.954 23.971 ;
     RECT  24.516 23.899 25.074 24.077 ;
     RECT  12.816 23.927 13.662 24.089 ;
     RECT  15.915 23.395 16.254 24.097 ;
     RECT  22.32 23.431 23.13 24.133 ;
     RECT  22.32 24.133 23.382 24.221 ;
     RECT  15.915 24.097 16.866 24.269 ;
     RECT  25.092 24.097 25.11 24.331 ;
     RECT  18.615 23.971 19.062 24.359 ;
     RECT  3.96 23.645 11.43 24.395 ;
     RECT  0.144 24.331 0.162 24.461 ;
     RECT  4.032 24.395 11.43 24.511 ;
     RECT  4.032 24.511 11.718 24.709 ;
     RECT  12.816 24.089 13.518 24.737 ;
     RECT  4.032 24.709 11.79 24.809 ;
     RECT  17.748 24.781 17.766 24.899 ;
     RECT  14.796 24.979 14.814 25.079 ;
     RECT  12.816 24.737 13.497 25.141 ;
     RECT  2.304 23.117 3.222 25.177 ;
     RECT  4.032 24.809 11.538 25.177 ;
     RECT  12.564 25.141 13.497 25.241 ;
     RECT  2.304 25.177 11.538 25.439 ;
     RECT  25.092 24.331 25.146 25.483 ;
     RECT  14.832 25.411 14.85 25.511 ;
     RECT  17.28 25.447 17.298 25.619 ;
     RECT  25.092 25.483 25.182 25.805 ;
     RECT  2.304 25.439 11.034 25.979 ;
     RECT  23.94 24.871 23.958 26.237 ;
     RECT  15.915 24.269 16.197 26.257 ;
     RECT  21.315 22.061 21.597 26.257 ;
     RECT  22.32 24.221 22.95 26.257 ;
     RECT  15.336 26.257 16.197 26.293 ;
     RECT  12.06 26.365 12.078 26.401 ;
     RECT  12.816 25.241 13.497 26.401 ;
     RECT  2.304 25.979 3.258 26.491 ;
     RECT  15.264 26.293 16.197 26.519 ;
     RECT  15.915 26.519 16.197 26.527 ;
     RECT  15.915 26.527 16.902 26.627 ;
     RECT  2.268 26.491 3.258 26.663 ;
     RECT  3.996 25.979 11.034 26.789 ;
     RECT  21.315 26.257 22.95 26.789 ;
     RECT  25.092 25.805 25.146 26.813 ;
     RECT  2.304 26.663 3.258 27.203 ;
     RECT  15.915 26.627 16.65 27.239 ;
     RECT  0.144 27.115 0.162 27.245 ;
     RECT  12.06 26.401 13.497 27.329 ;
     RECT  25.092 26.813 25.11 27.389 ;
     RECT  23.94 27.301 23.958 27.533 ;
     RECT  11.916 27.481 11.934 27.599 ;
     RECT  14.832 27.031 14.85 27.599 ;
     RECT  17.496 27.571 17.514 27.607 ;
     RECT  20.196 23.863 20.214 27.607 ;
     RECT  4.068 26.789 10.998 27.643 ;
     RECT  20.196 27.607 20.538 27.643 ;
     RECT  21.315 26.789 22.878 27.643 ;
     RECT  17.316 27.607 17.514 27.671 ;
     RECT  20.196 27.643 22.878 27.677 ;
     RECT  4.068 27.643 11.43 27.715 ;
     RECT  17.316 27.671 17.334 27.779 ;
     RECT  21.096 27.677 22.878 27.821 ;
     RECT  21.096 27.821 21.597 27.965 ;
     RECT  24.516 27.841 24.534 28.109 ;
     RECT  25.092 28.111 25.11 28.253 ;
     RECT  0.18 28.363 0.198 28.493 ;
     RECT  15.915 27.239 16.197 28.795 ;
     RECT  12.816 27.329 13.497 28.957 ;
     RECT  15.915 28.795 16.83 28.957 ;
     RECT  20.196 27.677 20.214 28.957 ;
     RECT  21.315 27.965 21.597 28.957 ;
     RECT  14.832 28.957 14.85 29.057 ;
     RECT  20.196 28.957 21.597 29.057 ;
     RECT  3.996 27.715 11.43 29.101 ;
     RECT  2.304 27.203 3.222 29.129 ;
     RECT  12.816 28.957 13.95 29.129 ;
     RECT  15.915 28.957 17.118 29.219 ;
     RECT  3.996 29.101 11.79 29.327 ;
     RECT  15.915 29.219 16.197 29.335 ;
     RECT  3.996 29.327 11.394 29.363 ;
     RECT  12.816 29.129 13.842 29.371 ;
     RECT  0.54 28.795 0.558 29.405 ;
     RECT  24.516 28.957 24.534 29.461 ;
     RECT  3.996 29.363 11.07 29.489 ;
     RECT  22.32 27.821 22.878 29.497 ;
     RECT  18.615 24.359 18.897 29.731 ;
     RECT  15.264 29.335 16.197 29.759 ;
     RECT  17.1 29.219 17.118 29.759 ;
     RECT  0.144 29.659 0.162 29.789 ;
     RECT  18.615 29.731 19.098 29.803 ;
     RECT  20.196 29.057 20.214 29.911 ;
     RECT  2.415 29.129 3.222 29.947 ;
     RECT  24.516 29.461 24.57 29.981 ;
     RECT  14.832 29.911 14.85 30.029 ;
     RECT  20.16 29.911 20.214 30.037 ;
     RECT  21.096 29.057 21.597 30.037 ;
     RECT  22.32 29.497 23.382 30.037 ;
     RECT  24.516 29.981 24.534 30.037 ;
     RECT  4.104 29.489 11.07 30.077 ;
     RECT  22.32 30.037 24.534 30.125 ;
     RECT  12.564 29.371 13.842 30.181 ;
     RECT  20.16 30.037 21.597 30.209 ;
     RECT  11.952 30.181 14.814 30.299 ;
     RECT  23.94 30.125 24.534 30.413 ;
     RECT  18.252 29.803 19.098 30.461 ;
     RECT  25.74 30.427 25.758 30.557 ;
     RECT  4.104 30.077 11.034 30.577 ;
     RECT  18.288 30.461 19.098 30.577 ;
     RECT  20.16 30.209 20.214 30.577 ;
     RECT  23.94 30.413 24.03 30.701 ;
     RECT  22.32 30.125 22.914 30.713 ;
     RECT  18.288 30.577 20.214 30.749 ;
     RECT  11.952 30.299 13.734 30.911 ;
     RECT  0.144 30.811 0.162 30.941 ;
     RECT  18.288 30.749 18.897 30.989 ;
     RECT  3.96 30.577 11.034 30.991 ;
     RECT  20.196 30.749 20.214 31.117 ;
     RECT  21.096 30.209 21.597 31.117 ;
     RECT  17.388 31.081 17.406 31.181 ;
     RECT  2.304 29.947 3.222 31.261 ;
     RECT  3.96 30.991 11.466 31.261 ;
     RECT  23.94 30.701 23.958 31.277 ;
     RECT  14.796 30.299 14.814 31.289 ;
     RECT  2.304 31.261 11.466 31.379 ;
     RECT  20.196 31.117 21.597 31.421 ;
     RECT  21.315 31.421 21.597 31.435 ;
     RECT  22.32 30.713 22.878 31.435 ;
     RECT  14.904 31.387 14.922 31.559 ;
     RECT  2.304 31.379 3.222 31.723 ;
     RECT  25.092 31.189 25.11 31.729 ;
     RECT  3.96 31.379 11.466 31.801 ;
     RECT  12.42 30.911 13.734 31.801 ;
     RECT  2.268 31.723 3.222 31.853 ;
     RECT  21.315 31.435 22.878 31.853 ;
     RECT  20.196 31.421 20.538 31.997 ;
     RECT  3.96 31.801 13.734 32.189 ;
     RECT  15.915 29.759 16.197 32.197 ;
     RECT  25.092 31.729 25.146 32.233 ;
     RECT  24.516 32.233 25.146 32.299 ;
     RECT  15.408 32.197 16.197 32.369 ;
     RECT  0.144 32.299 0.162 32.429 ;
     RECT  24.516 32.299 25.758 32.429 ;
     RECT  3.96 32.189 13.698 32.459 ;
     RECT  2.304 31.853 3.222 32.827 ;
     RECT  3.96 32.459 11.97 32.827 ;
     RECT  2.304 32.827 11.97 32.999 ;
     RECT  2.304 32.999 11.898 33.071 ;
     RECT  3.996 33.071 11.898 33.341 ;
     RECT  2.304 33.071 3.258 33.377 ;
     RECT  21.315 31.853 21.597 33.403 ;
     RECT  14.832 33.307 14.85 33.437 ;
     RECT  21.204 33.403 21.597 33.449 ;
     RECT  24.516 32.429 25.218 33.511 ;
     RECT  23.94 33.511 25.218 33.581 ;
     RECT  12.744 32.459 13.698 33.691 ;
     RECT  23.94 33.581 24.534 33.725 ;
     RECT  24.516 33.725 24.534 33.869 ;
     RECT  18.615 30.989 18.897 33.961 ;
     RECT  0.54 33.349 0.558 34.013 ;
     RECT  0.144 34.267 0.162 34.397 ;
     RECT  3.996 33.341 11.718 34.411 ;
     RECT  12.744 33.691 14.238 34.411 ;
     RECT  2.304 33.377 3.222 34.501 ;
     RECT  3.996 34.411 14.238 34.501 ;
     RECT  2.304 34.501 14.238 34.619 ;
     RECT  25.812 34.267 25.83 34.619 ;
     RECT  17.28 34.501 17.298 34.735 ;
     RECT  15.915 32.369 16.197 34.933 ;
     RECT  0.18 34.843 0.198 34.973 ;
     RECT  20.196 31.997 20.214 34.987 ;
     RECT  17.28 34.735 17.37 35.041 ;
     RECT  18.615 33.961 19.17 35.041 ;
     RECT  4.068 34.619 14.238 35.069 ;
     RECT  9.864 35.069 14.238 35.131 ;
     RECT  20.196 34.987 20.502 35.131 ;
     RECT  21.315 33.449 21.597 35.131 ;
     RECT  20.196 35.131 21.597 35.195 ;
     RECT  9.864 35.131 14.85 35.597 ;
     RECT  21.204 35.195 21.597 35.609 ;
     RECT  21.315 35.609 21.597 35.845 ;
     RECT  22.32 31.853 22.878 35.845 ;
     RECT  0.18 35.755 0.198 35.885 ;
     RECT  21.315 35.845 22.878 35.885 ;
     RECT  22.32 35.885 22.878 35.995 ;
     RECT  23.904 34.843 23.922 35.995 ;
     RECT  4.068 35.069 8.874 36.049 ;
     RECT  9.864 35.597 14.814 36.049 ;
     RECT  4.068 36.049 14.814 36.347 ;
     RECT  4.068 36.347 14.238 36.355 ;
     RECT  22.32 35.995 23.922 36.427 ;
     RECT  25.056 35.419 25.074 36.427 ;
     RECT  25.812 36.139 25.83 36.779 ;
     RECT  3.996 36.355 14.238 36.895 ;
     RECT  22.32 36.427 25.074 36.907 ;
     RECT  14.976 36.391 14.994 36.931 ;
     RECT  15.804 34.933 16.197 36.931 ;
     RECT  17.28 35.041 19.17 36.931 ;
     RECT  22.32 36.907 25.758 37.037 ;
     RECT  3.96 36.895 14.238 37.201 ;
     RECT  14.976 36.931 16.197 37.201 ;
     RECT  21.315 35.885 21.597 37.291 ;
     RECT  22.32 37.037 25.074 37.291 ;
     RECT  17.28 36.931 19.386 37.327 ;
     RECT  16.992 37.327 19.386 37.427 ;
     RECT  0.144 36.907 0.162 37.613 ;
     RECT  3.96 37.201 16.197 37.733 ;
     RECT  2.304 34.619 3.222 37.769 ;
     RECT  21.315 37.291 25.074 38.011 ;
     RECT  3.996 37.733 16.197 38.129 ;
     RECT  21.315 38.011 25.758 38.141 ;
     RECT  17.1 37.427 19.386 38.281 ;
     RECT  20.196 35.195 20.214 38.281 ;
     RECT  22.32 38.141 25.758 38.309 ;
     RECT  17.1 38.281 20.214 38.399 ;
     RECT  0.18 38.299 0.198 38.429 ;
     RECT  4.068 38.129 16.197 38.515 ;
     RECT  21.315 38.141 21.597 38.551 ;
     RECT  17.1 38.399 19.386 38.579 ;
     RECT  2.415 37.769 3.222 38.587 ;
     RECT  17.172 38.579 19.386 38.669 ;
     RECT  23.94 38.309 25.758 38.705 ;
     RECT  4.068 38.515 16.254 39.055 ;
     RECT  23.94 38.705 24.462 39.119 ;
     RECT  0.144 38.779 0.162 39.149 ;
     RECT  25.74 38.705 25.758 39.197 ;
     RECT  17.28 38.669 19.386 39.209 ;
     RECT  17.28 39.209 19.17 39.479 ;
     RECT  2.304 38.587 3.222 39.559 ;
     RECT  3.996 39.055 16.254 39.559 ;
     RECT  22.32 38.309 22.95 39.721 ;
     RECT  23.94 39.119 23.958 39.721 ;
     RECT  2.304 39.559 16.254 39.749 ;
     RECT  17.496 39.479 19.17 39.749 ;
     RECT  3.96 39.749 16.254 39.821 ;
     RECT  6.336 39.821 16.254 39.929 ;
     RECT  17.892 39.749 19.17 40.019 ;
     RECT  21.06 38.551 21.597 40.027 ;
     RECT  22.32 39.721 23.958 40.027 ;
     RECT  0.324 39.883 0.342 40.061 ;
     RECT  21.06 40.027 23.958 40.061 ;
     RECT  18.18 40.019 19.17 40.127 ;
     RECT  18.432 40.127 19.17 40.171 ;
     RECT  14.832 39.929 16.254 40.441 ;
     RECT  3.96 39.821 5.562 40.555 ;
     RECT  6.336 39.929 14.058 40.555 ;
     RECT  0.144 40.459 0.162 40.589 ;
     RECT  21.06 40.061 23.382 40.637 ;
     RECT  21.06 40.637 22.878 40.781 ;
     RECT  18.432 40.171 19.422 40.829 ;
     RECT  14.832 40.441 16.398 40.837 ;
     RECT  23.94 40.873 23.958 40.909 ;
     RECT  14.832 40.837 16.866 41.009 ;
     RECT  25.092 40.027 25.11 41.069 ;
     RECT  14.832 41.009 16.197 41.099 ;
     RECT  21.06 40.781 21.597 41.099 ;
     RECT  3.96 40.555 14.058 41.135 ;
     RECT  23.94 40.909 24.03 41.357 ;
     RECT  14.832 41.099 14.994 41.369 ;
     RECT  18.432 40.829 18.897 41.369 ;
     RECT  20.196 38.399 20.214 41.377 ;
     RECT  22.32 40.781 22.878 41.377 ;
     RECT  6.372 41.135 14.058 41.501 ;
     RECT  19.872 41.377 20.214 41.549 ;
     RECT  17.028 41.521 17.046 41.639 ;
     RECT  3.96 41.135 5.562 41.675 ;
     RECT  11.952 41.501 14.058 41.741 ;
     RECT  22.32 41.377 23.382 41.789 ;
     RECT  12.744 41.741 14.058 41.791 ;
     RECT  14.832 41.369 14.886 41.791 ;
     RECT  19.944 41.549 20.214 41.981 ;
     RECT  4.068 41.675 5.562 42.061 ;
     RECT  6.372 41.501 10.926 42.061 ;
     RECT  0.144 41.947 0.162 42.077 ;
     RECT  12.744 41.791 14.886 42.179 ;
     RECT  21.096 41.099 21.597 42.187 ;
     RECT  22.32 41.789 22.878 42.187 ;
     RECT  21.096 42.187 22.878 42.215 ;
     RECT  25.092 42.151 25.11 42.259 ;
     RECT  21.315 42.215 22.878 42.365 ;
     RECT  2.304 39.749 3.222 42.457 ;
     RECT  4.068 42.061 10.926 42.457 ;
     RECT  25.092 42.259 25.83 42.653 ;
     RECT  2.304 42.457 10.926 42.691 ;
     RECT  11.952 41.741 11.97 42.691 ;
     RECT  22.32 42.365 22.878 42.763 ;
     RECT  0.54 42.601 0.558 42.797 ;
     RECT  14.868 42.179 14.886 42.797 ;
     RECT  2.304 42.691 11.97 42.871 ;
     RECT  12.744 42.179 14.13 42.871 ;
     RECT  25.092 42.653 25.758 42.941 ;
     RECT  15.915 41.099 16.197 43.105 ;
     RECT  25.74 42.941 25.758 43.229 ;
     RECT  2.304 42.871 14.13 43.259 ;
     RECT  22.32 42.763 22.95 43.303 ;
     RECT  12.492 43.259 13.698 43.373 ;
     RECT  22.32 43.303 23.382 43.517 ;
     RECT  12.816 43.373 13.698 43.529 ;
     RECT  15.408 43.105 16.197 43.645 ;
     RECT  2.304 43.259 11.538 43.681 ;
     RECT  15.084 43.645 16.197 43.771 ;
     RECT  21.315 42.365 21.597 43.771 ;
     RECT  2.268 43.681 11.538 43.799 ;
     RECT  2.268 43.799 3.258 43.805 ;
     RECT  24.516 43.069 24.534 43.807 ;
     RECT  21.204 43.771 21.597 43.808 ;
     RECT  14.832 43.771 16.197 43.871 ;
     RECT  23.94 43.807 24.534 44.041 ;
     RECT  23.94 44.041 25.11 44.093 ;
     RECT  4.032 43.799 11.538 44.113 ;
     RECT  18.615 41.369 18.897 44.221 ;
     RECT  4.032 44.113 12.042 44.311 ;
     RECT  12.816 43.529 13.554 44.311 ;
     RECT  17.676 43.681 17.694 44.339 ;
     RECT  14.832 43.871 14.85 44.347 ;
     RECT  14.364 44.347 14.85 44.375 ;
     RECT  18.615 44.221 19.17 44.375 ;
     RECT  4.032 44.311 13.554 44.491 ;
     RECT  14.364 44.375 14.814 44.519 ;
     RECT  4.032 44.491 13.59 44.609 ;
     RECT  22.32 43.517 22.95 44.617 ;
     RECT  4.032 44.609 13.497 44.681 ;
     RECT  2.304 43.805 3.258 45.023 ;
     RECT  18.615 44.375 18.897 45.193 ;
     RECT  22.32 44.617 23.454 45.245 ;
     RECT  24.516 44.093 25.11 45.389 ;
     RECT  14.796 44.519 14.814 45.419 ;
     RECT  25.092 45.389 25.11 45.463 ;
     RECT  2.415 45.023 3.258 45.571 ;
     RECT  4.068 44.681 13.497 45.571 ;
     RECT  18.252 45.193 18.897 45.689 ;
     RECT  2.415 45.571 13.497 45.725 ;
     RECT  0.144 45.355 0.162 45.773 ;
     RECT  2.415 45.725 3.258 45.931 ;
     RECT  3.996 45.725 13.497 45.959 ;
     RECT  2.304 45.931 3.258 46.031 ;
     RECT  12.744 45.959 13.497 46.067 ;
     RECT  15.084 46.003 15.102 46.237 ;
     RECT  15.915 43.871 16.197 46.237 ;
     RECT  3.996 45.959 12.006 46.265 ;
     RECT  2.304 46.031 2.862 46.409 ;
     RECT  15.084 46.237 16.197 46.471 ;
     RECT  23.94 45.427 23.958 46.471 ;
     RECT  10.152 46.265 12.006 46.499 ;
     RECT  5.115 46.265 9.306 46.535 ;
     RECT  2.415 46.409 2.862 46.607 ;
     RECT  5.115 46.535 6.57 46.607 ;
     RECT  14.976 46.471 16.197 46.679 ;
     RECT  23.94 46.471 23.994 46.685 ;
     RECT  11.988 46.499 12.006 46.769 ;
     RECT  15.516 46.679 16.197 46.769 ;
     RECT  21.315 43.808 21.597 46.777 ;
     RECT  22.32 45.245 22.878 46.777 ;
     RECT  3.996 46.265 4.014 46.805 ;
     RECT  23.976 46.685 23.994 46.829 ;
     RECT  7.704 46.535 9.306 46.841 ;
     RECT  25.092 45.463 25.146 46.939 ;
     RECT  9.288 46.841 9.306 47.039 ;
     RECT  25.092 46.939 25.83 47.111 ;
     RECT  10.152 46.499 11.034 47.191 ;
     RECT  7.704 46.841 8.154 47.281 ;
     RECT  21.315 46.777 22.878 47.281 ;
     RECT  5.115 46.607 6.462 47.309 ;
     RECT  9.576 47.191 11.034 47.309 ;
     RECT  12.816 46.067 13.497 47.309 ;
     RECT  21.096 47.281 22.878 47.405 ;
     RECT  10.152 47.309 11.034 47.417 ;
     RECT  7.416 47.281 8.154 47.453 ;
     RECT  11.916 47.389 11.934 47.461 ;
     RECT  20.196 41.981 20.214 47.461 ;
     RECT  21.096 47.405 21.597 47.461 ;
     RECT  11.844 47.461 11.934 47.489 ;
     RECT  7.815 47.453 8.154 47.579 ;
     RECT  20.196 47.461 21.597 47.579 ;
     RECT  22.32 47.405 22.878 47.579 ;
     RECT  25.092 47.111 25.758 47.693 ;
     RECT  23.94 47.551 23.958 47.731 ;
     RECT  11.844 47.489 11.862 47.741 ;
     RECT  22.824 47.579 22.878 47.821 ;
     RECT  23.94 47.731 24.57 47.821 ;
     RECT  25.74 47.693 25.758 47.837 ;
     RECT  6.444 47.309 6.462 47.849 ;
     RECT  21.096 47.579 21.597 47.981 ;
     RECT  20.196 47.579 20.214 48.119 ;
     RECT  22.824 47.821 24.57 48.125 ;
     RECT  12.852 47.309 13.497 48.389 ;
     RECT  22.824 48.125 22.842 48.461 ;
     RECT  21.315 47.981 21.597 48.541 ;
     RECT  23.94 48.125 24.57 48.557 ;
     RECT  10.152 47.417 10.797 48.569 ;
     RECT  23.976 48.557 24.57 48.631 ;
     RECT  21.315 48.541 21.906 48.659 ;
     RECT  23.976 48.631 25.11 48.701 ;
     RECT  23.976 48.701 23.994 48.845 ;
     RECT  25.092 48.701 25.11 48.989 ;
     RECT  2.415 46.607 2.697 49.427 ;
     RECT  5.115 47.309 5.397 49.427 ;
     RECT  7.815 47.579 8.097 49.427 ;
     RECT  10.515 48.569 10.797 49.427 ;
     RECT  13.215 48.389 13.497 49.427 ;
     RECT  15.915 46.769 16.197 49.427 ;
     RECT  18.615 45.689 18.897 49.427 ;
     RECT  21.315 48.659 21.597 49.427 ;
     RECT  2.415 49.427 2.505 49.697 ;
     RECT  5.115 49.427 5.205 49.697 ;
     RECT  7.815 49.427 7.905 49.697 ;
     RECT  10.515 49.427 10.605 49.697 ;
     RECT  13.215 49.427 13.305 49.697 ;
     RECT  15.915 49.427 16.005 49.697 ;
     RECT  18.615 49.427 18.705 49.697 ;
     RECT  21.315 49.427 21.405 49.697 ;
    LAYER M4 ;
     RECT  0.06 3.888 2.408 46.392 ;
     RECT  2.408 2.148 2.512 49.692 ;
     RECT  2.512 2.418 2.704 49.422 ;
     RECT  2.704 3.888 2.909 46.392 ;
     RECT  2.909 4.08 4.025 46.392 ;
     RECT  4.025 4.08 5.108 16.392 ;
     RECT  4.025 17.472 5.108 24.984 ;
     RECT  4.025 26.304 5.108 46.104 ;
     RECT  5.108 2.148 5.212 49.692 ;
     RECT  5.212 2.418 5.404 49.422 ;
     RECT  5.404 31.392 5.573 44.664 ;
     RECT  5.404 4.176 5.969 5.016 ;
     RECT  5.404 6.048 6.131 30.408 ;
     RECT  5.404 45.744 6.257 46.2 ;
     RECT  5.573 32.496 6.373 44.664 ;
     RECT  6.257 46.176 6.437 46.2 ;
     RECT  6.373 32.496 6.46 45 ;
     RECT  5.969 4.704 6.833 5.016 ;
     RECT  6.833 4.8 7.808 5.016 ;
     RECT  6.131 6.048 7.808 16.392 ;
     RECT  6.131 17.472 7.808 30.408 ;
     RECT  5.573 31.392 7.808 31.512 ;
     RECT  6.46 32.496 7.808 44.088 ;
     RECT  7.405 47.424 7.808 47.448 ;
     RECT  7.808 2.148 7.912 49.692 ;
     RECT  7.912 2.418 8.104 49.422 ;
     RECT  8.104 4.464 8.165 6.888 ;
     RECT  8.165 4.464 8.243 6.312 ;
     RECT  8.104 44.64 8.243 44.664 ;
     RECT  8.104 45.744 8.243 47.448 ;
     RECT  8.243 4.656 8.273 4.68 ;
     RECT  8.104 11.232 8.309 13.464 ;
     RECT  8.104 14.928 8.381 15.336 ;
     RECT  8.104 19.872 8.489 21.048 ;
     RECT  8.309 13.104 8.669 13.464 ;
     RECT  8.104 25.104 8.957 26.04 ;
     RECT  8.104 31.44 8.993 31.512 ;
     RECT  8.669 13.44 9.029 13.464 ;
     RECT  8.381 15.072 9.029 15.336 ;
     RECT  8.104 40.992 9.029 41.016 ;
     RECT  8.993 31.488 9.065 31.512 ;
     RECT  9.029 15.264 9.169 15.336 ;
     RECT  8.104 18.72 9.245 18.744 ;
     RECT  8.957 25.104 9.281 25.8 ;
     RECT  9.097 37.44 9.281 37.464 ;
     RECT  8.309 11.232 9.353 11.736 ;
     RECT  8.489 20.64 9.389 21.048 ;
     RECT  8.104 17.472 9.421 17.496 ;
     RECT  9.353 11.28 9.425 11.736 ;
     RECT  9.169 15.264 9.497 15.624 ;
     RECT  9.497 15.264 9.533 15.336 ;
     RECT  9.421 17.088 9.533 17.496 ;
     RECT  9.493 21.888 9.961 21.912 ;
     RECT  8.104 28.464 10.177 30.072 ;
     RECT  9.281 25.776 10.249 25.8 ;
     RECT  10.213 40.032 10.429 40.056 ;
     RECT  8.104 3.408 10.508 3.432 ;
     RECT  10.357 8.736 10.508 8.76 ;
     RECT  9.425 11.616 10.508 11.736 ;
     RECT  9.533 15.264 10.508 15.288 ;
     RECT  9.533 17.472 10.508 17.496 ;
     RECT  9.529 19.344 10.508 19.368 ;
     RECT  9.389 20.64 10.508 20.712 ;
     RECT  9.961 21.888 10.508 21.96 ;
     RECT  10.249 25.776 10.508 26.28 ;
     RECT  10.177 28.464 10.508 30.168 ;
     RECT  10.429 39.6 10.508 40.056 ;
     RECT  8.243 47.424 10.508 47.448 ;
     RECT  10.508 2.148 10.612 49.692 ;
     RECT  10.612 2.148 10.804 49.422 ;
     RECT  10.804 26.256 10.829 26.328 ;
     RECT  10.309 0.096 10.835 0.12 ;
     RECT  10.804 3.408 10.865 3.432 ;
     RECT  10.804 20.16 10.901 20.664 ;
     RECT  10.804 21.936 10.937 21.96 ;
     RECT  10.829 26.256 10.937 26.28 ;
     RECT  10.804 28.464 10.937 30.792 ;
     RECT  10.937 29.328 11.009 30.792 ;
     RECT  10.933 1.728 11.017 1.752 ;
     RECT  10.804 17.136 11.081 18.456 ;
     RECT  11.009 29.328 11.081 30.072 ;
     RECT  10.804 32.832 11.833 32.856 ;
     RECT  10.804 39.072 11.833 40.056 ;
     RECT  10.804 41.472 11.833 41.496 ;
     RECT  10.804 47.424 11.833 47.448 ;
     RECT  11.833 32.304 11.869 32.856 ;
     RECT  10.804 37.44 11.869 37.992 ;
     RECT  10.804 44.64 11.869 44.664 ;
     RECT  10.804 10.848 11.873 10.872 ;
     RECT  10.804 5.76 11.905 6.36 ;
     RECT  10.804 7.344 11.905 9.816 ;
     RECT  10.804 35.232 11.905 35.736 ;
     RECT  11.869 36.864 11.905 37.992 ;
     RECT  11.081 18.432 11.941 18.456 ;
     RECT  10.901 20.16 11.941 20.184 ;
     RECT  11.905 35.232 11.941 37.992 ;
     RECT  11.833 39.072 11.941 41.496 ;
     RECT  11.941 22.464 12.049 22.488 ;
     RECT  10.804 15.552 12.265 15.576 ;
     RECT  11.081 17.136 12.265 17.208 ;
     RECT  11.941 35.232 12.265 41.928 ;
     RECT  11.905 5.76 12.301 9.816 ;
     RECT  11.869 32.304 12.409 33.336 ;
     RECT  11.941 18.432 12.877 20.184 ;
     RECT  12.049 21.792 12.877 22.488 ;
     RECT  12.409 31.44 13.129 33.336 ;
     RECT  12.265 34.416 13.129 41.928 ;
     RECT  12.301 5.472 13.208 9.816 ;
     RECT  12.913 12.528 13.208 12.552 ;
     RECT  12.265 15.552 13.208 17.208 ;
     RECT  12.877 18.432 13.208 22.488 ;
     RECT  10.804 23.616 13.208 23.64 ;
     RECT  10.804 24.624 13.208 24.648 ;
     RECT  13.129 31.44 13.208 41.928 ;
     RECT  10.804 43.056 13.208 43.656 ;
     RECT  11.869 44.64 13.208 45.528 ;
     RECT  11.833 47.424 13.208 47.736 ;
     RECT  13.208 2.148 13.312 49.692 ;
     RECT  13.312 2.418 13.504 49.422 ;
     RECT  13.504 12.528 14.677 12.552 ;
     RECT  13.504 15.552 14.713 17.448 ;
     RECT  13.504 5.328 14.821 9.816 ;
     RECT  14.713 15.264 15.613 17.448 ;
     RECT  13.504 18.432 15.613 20.184 ;
     RECT  14.677 12.528 15.721 12.888 ;
     RECT  13.504 14.112 15.721 14.136 ;
     RECT  14.821 5.232 15.908 9.816 ;
     RECT  15.721 12.528 15.908 14.136 ;
     RECT  15.613 15.264 15.908 20.184 ;
     RECT  13.504 21.744 15.908 22.488 ;
     RECT  13.504 23.616 15.908 23.64 ;
     RECT  13.504 24.624 15.908 24.648 ;
     RECT  13.504 31.44 15.908 45.528 ;
     RECT  13.504 47.424 15.908 47.736 ;
     RECT  15.908 2.148 16.012 49.692 ;
     RECT  16.012 2.418 16.204 49.422 ;
     RECT  16.204 12.528 18.205 14.136 ;
     RECT  18.241 30.432 18.277 30.456 ;
     RECT  16.204 31.44 18.277 45.528 ;
     RECT  16.204 5.232 18.608 10.68 ;
     RECT  18.205 11.664 18.608 14.136 ;
     RECT  16.204 15.264 18.608 20.184 ;
     RECT  16.204 21.744 18.608 22.488 ;
     RECT  16.204 23.616 18.608 23.64 ;
     RECT  16.204 24.624 18.608 24.648 ;
     RECT  18.277 30.432 18.608 45.528 ;
     RECT  16.204 47.424 18.608 47.736 ;
     RECT  18.608 2.148 18.712 49.692 ;
     RECT  18.712 2.418 18.904 49.422 ;
     RECT  18.904 15.264 21.085 20.184 ;
     RECT  18.904 21.744 21.085 22.488 ;
     RECT  20.509 27.648 21.085 27.672 ;
     RECT  18.904 30.432 21.085 45.528 ;
     RECT  18.904 47.424 21.085 47.736 ;
     RECT  18.904 5.328 21.308 10.68 ;
     RECT  18.904 11.664 21.308 14.136 ;
     RECT  21.085 15.264 21.308 22.488 ;
     RECT  18.904 23.616 21.308 23.64 ;
     RECT  18.904 24.624 21.308 24.648 ;
     RECT  21.085 27.648 21.308 27.96 ;
     RECT  21.085 29.808 21.308 45.528 ;
     RECT  21.085 47.424 21.308 47.976 ;
     RECT  21.308 2.148 21.412 49.692 ;
     RECT  21.412 2.418 21.604 49.422 ;
     RECT  21.604 44.784 22.705 45.528 ;
     RECT  21.604 29.808 22.777 43.8 ;
     RECT  21.604 26.352 22.813 27.96 ;
     RECT  22.777 29.664 22.813 43.8 ;
     RECT  22.705 44.784 22.813 46.392 ;
     RECT  21.604 15.264 23.353 22.488 ;
     RECT  21.604 23.616 23.353 23.64 ;
     RECT  21.604 24.624 23.353 24.648 ;
     RECT  21.604 47.376 23.353 47.976 ;
     RECT  23.353 15.12 23.929 24.648 ;
     RECT  22.813 26.064 23.929 27.96 ;
     RECT  22.813 29.664 23.929 46.392 ;
     RECT  23.353 47.376 23.929 48.12 ;
     RECT  23.929 29.664 23.965 48.552 ;
     RECT  23.929 15.12 24.505 27.96 ;
     RECT  23.965 29.664 24.505 48.84 ;
     RECT  21.604 5.328 25.081 10.68 ;
     RECT  21.604 11.664 25.081 14.136 ;
     RECT  24.505 15.12 25.081 28.104 ;
     RECT  24.505 29.52 25.081 48.84 ;
     RECT  25.081 5.328 25.884 28.248 ;
     RECT  25.081 29.52 25.884 48.984 ;
    LAYER M5 ;
     RECT  10.8 0.016 10.968 0.085 ;
     RECT  10.32 0.085 10.968 1.763 ;
     RECT  2.4 2.137 2.52 2.151 ;
     RECT  5.1 2.137 5.22 2.151 ;
     RECT  7.8 2.137 7.92 2.151 ;
     RECT  13.2 2.137 13.32 2.151 ;
     RECT  15.9 2.137 16.02 2.151 ;
     RECT  18.6 2.137 18.72 2.151 ;
     RECT  21.3 2.137 21.42 2.151 ;
     RECT  7.8 2.151 8.112 3.397 ;
     RECT  7.8 3.397 8.232 6.323 ;
     RECT  25.728 7.237 25.752 7.333 ;
     RECT  25.584 7.333 25.752 7.429 ;
     RECT  25.584 7.429 25.8 7.475 ;
     RECT  2.4 2.151 2.712 7.717 ;
     RECT  2.4 7.717 2.856 7.907 ;
     RECT  5.1 2.151 5.412 7.957 ;
     RECT  25.776 7.475 25.8 8.677 ;
     RECT  4.704 7.957 5.412 11.413 ;
     RECT  4.704 11.413 6.072 11.459 ;
     RECT  2.4 7.907 2.712 11.701 ;
     RECT  2.304 11.701 2.712 11.843 ;
     RECT  25.728 8.677 25.8 13.139 ;
     RECT  25.728 13.139 25.752 13.715 ;
     RECT  5.1 11.459 6.072 17.029 ;
     RECT  2.4 11.843 2.712 18.517 ;
     RECT  2.304 18.517 2.712 18.707 ;
     RECT  10.32 1.763 10.812 19.333 ;
     RECT  2.4 18.707 2.712 20.677 ;
     RECT  2.304 20.677 2.712 21.059 ;
     RECT  9.552 19.333 10.812 21.923 ;
     RECT  2.4 21.059 2.712 23.125 ;
     RECT  2.304 23.125 2.712 23.315 ;
     RECT  0.144 23.653 0.168 23.939 ;
     RECT  5.1 17.029 6.12 25.765 ;
     RECT  10.32 21.923 10.812 25.811 ;
     RECT  5.1 25.765 6.456 25.907 ;
     RECT  0.144 26.197 0.168 26.339 ;
     RECT  5.1 25.907 6.12 27.589 ;
     RECT  5.1 27.589 6.312 28.595 ;
     RECT  5.1 28.595 6.12 33.061 ;
     RECT  5.1 33.061 6.456 33.299 ;
     RECT  14.784 35.509 14.808 35.747 ;
     RECT  6.432 33.299 6.456 37.237 ;
     RECT  6.432 37.237 6.552 37.283 ;
     RECT  13.2 2.151 13.512 37.957 ;
     RECT  13.2 37.957 13.608 38.147 ;
     RECT  0.144 40.021 0.168 40.163 ;
     RECT  5.1 33.299 5.412 40.981 ;
     RECT  4.56 40.981 5.412 41.699 ;
     RECT  6.528 37.283 6.552 42.803 ;
     RECT  7.8 6.323 8.112 43.333 ;
     RECT  7.392 43.333 8.112 43.571 ;
     RECT  2.4 23.315 2.712 44.437 ;
     RECT  2.304 44.437 2.712 44.627 ;
     RECT  7.8 43.571 8.112 44.629 ;
     RECT  6.384 44.965 6.408 46.211 ;
     RECT  7.8 44.629 8.232 46.835 ;
     RECT  2.4 44.627 2.712 49.689 ;
     RECT  5.1 41.699 5.412 49.689 ;
     RECT  7.8 46.835 8.112 49.689 ;
     RECT  10.5 25.811 10.812 49.689 ;
     RECT  13.2 38.147 13.512 49.689 ;
     RECT  15.9 2.151 16.212 49.689 ;
     RECT  18.6 2.151 18.912 49.689 ;
     RECT  21.3 2.151 21.612 49.689 ;
     RECT  2.4 49.689 2.52 49.703 ;
     RECT  5.1 49.689 5.22 49.703 ;
     RECT  7.8 49.689 7.92 49.703 ;
     RECT  10.5 49.689 10.62 49.703 ;
     RECT  13.2 49.689 13.32 49.703 ;
     RECT  15.9 49.689 16.02 49.703 ;
     RECT  18.6 49.689 18.72 49.703 ;
     RECT  21.3 49.689 21.42 49.703 ;
  END
END qkd_astk_rly_296_fl
END LIBRARY
